VERSION 5.7 ;
  NOWIREEXTENSIONATPIN ON ;
  DIVIDERCHAR "/" ;
  BUSBITCHARS "[]" ;
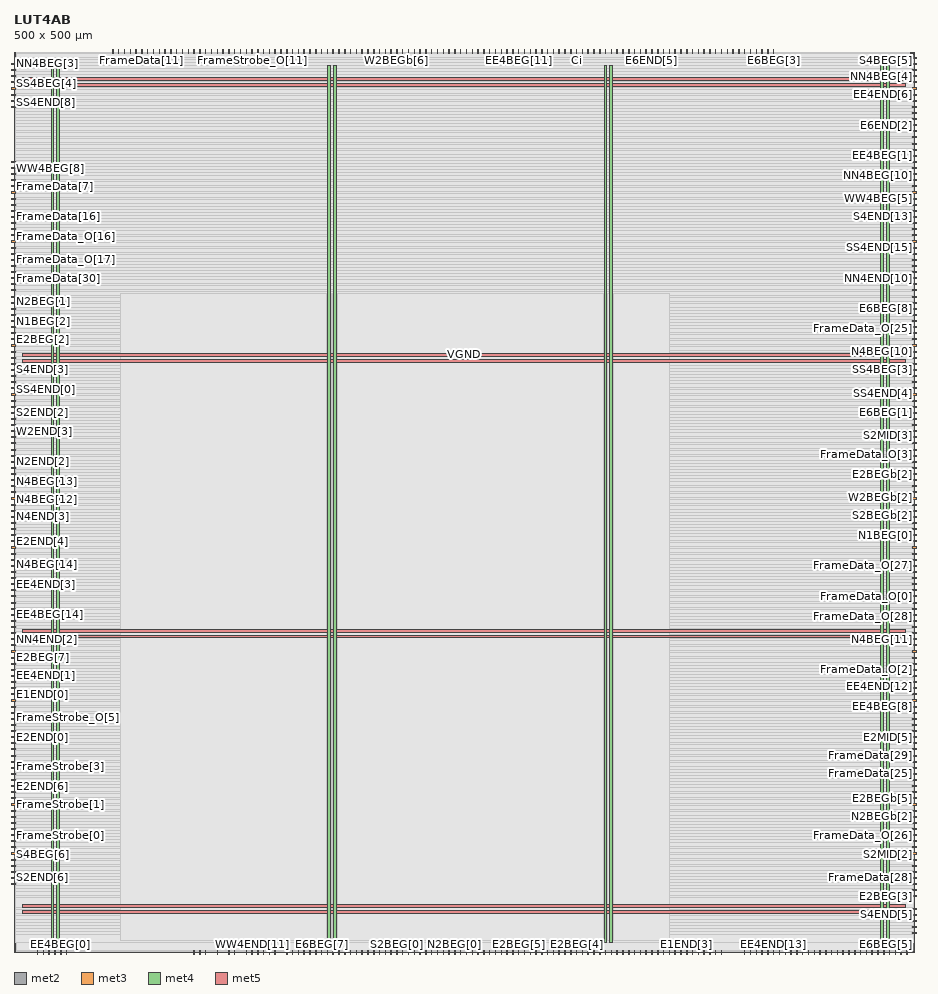
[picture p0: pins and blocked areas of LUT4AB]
MACRO LUT4AB
  CLASS BLOCK ;
  FOREIGN LUT4AB ;
  ORIGIN 0.000 0.000 ;
  SIZE 500.000 BY 500.000 ;
  PIN Ci
    DIRECTION INPUT ;
    USE SIGNAL ;
    ANTENNAGATEAREA 0.742500 ;
    PORT
      LAYER met2 ;
        RECT 312.430 499.200 312.710 501.500 ;
    END
  END Ci
  PIN Co
    DIRECTION OUTPUT ;
    USE SIGNAL ;
    ANTENNADIFFAREA 0.445500 ;
    PORT
      LAYER met2 ;
        RECT 235.150 499.200 235.430 501.500 ;
    END
  END Co
  PIN E1BEG[0]
    DIRECTION OUTPUT ;
    USE SIGNAL ;
    ANTENNADIFFAREA 1.336500 ;
    PORT
      LAYER met2 ;
        RECT 296.330 499.200 296.610 501.500 ;
    END
  END E1BEG[0]
  PIN E1BEG[1]
    DIRECTION OUTPUT ;
    USE SIGNAL ;
    ANTENNADIFFAREA 0.445500 ;
    PORT
      LAYER met2 ;
        RECT 257.690 -1.500 257.970 0.800 ;
    END
  END E1BEG[1]
  PIN E1BEG[2]
    DIRECTION OUTPUT ;
    USE SIGNAL ;
    ANTENNADIFFAREA 1.782000 ;
    PORT
      LAYER met3 ;
        RECT -1.500 438.640 0.800 439.240 ;
    END
  END E1BEG[2]
  PIN E1BEG[3]
    DIRECTION OUTPUT ;
    USE SIGNAL ;
    ANTENNADIFFAREA 1.336500 ;
    PORT
      LAYER met2 ;
        RECT 206.170 499.200 206.450 501.500 ;
    END
  END E1BEG[3]
  PIN E1END[0]
    DIRECTION INPUT ;
    USE SIGNAL ;
    ANTENNAGATEAREA 0.247500 ;
    PORT
      LAYER met3 ;
        RECT -1.500 142.840 0.800 143.440 ;
    END
  END E1END[0]
  PIN E1END[1]
    DIRECTION INPUT ;
    USE SIGNAL ;
    ANTENNAGATEAREA 0.426000 ;
    PORT
      LAYER met2 ;
        RECT 141.770 -1.500 142.050 0.800 ;
    END
  END E1END[1]
  PIN E1END[2]
    DIRECTION INPUT ;
    USE SIGNAL ;
    ANTENNAGATEAREA 0.159000 ;
    PORT
      LAYER met3 ;
        RECT -1.500 37.440 0.800 38.040 ;
    END
  END E1END[2]
  PIN E1END[3]
    DIRECTION INPUT ;
    USE SIGNAL ;
    ANTENNAGATEAREA 0.126000 ;
    PORT
      LAYER met2 ;
        RECT 373.610 -1.500 373.890 0.800 ;
    END
  END E1END[3]
  PIN E2BEG[0]
    DIRECTION OUTPUT ;
    USE SIGNAL ;
    ANTENNADIFFAREA 1.782000 ;
    PORT
      LAYER met2 ;
        RECT 151.430 -1.500 151.710 0.800 ;
    END
  END E2BEG[0]
  PIN E2BEG[1]
    DIRECTION OUTPUT ;
    USE SIGNAL ;
    ANTENNADIFFAREA 1.782000 ;
    PORT
      LAYER met3 ;
        RECT -1.500 346.840 0.800 347.440 ;
    END
  END E2BEG[1]
  PIN E2BEG[2]
    DIRECTION OUTPUT ;
    USE SIGNAL ;
    ANTENNADIFFAREA 1.782000 ;
    PORT
      LAYER met3 ;
        RECT -1.500 340.040 0.800 340.640 ;
    END
  END E2BEG[2]
  PIN E2BEG[3]
    DIRECTION OUTPUT ;
    USE SIGNAL ;
    ANTENNADIFFAREA 0.445500 ;
    PORT
      LAYER met3 ;
        RECT 499.200 30.640 501.500 31.240 ;
    END
  END E2BEG[3]
  PIN E2BEG[4]
    DIRECTION OUTPUT ;
    USE SIGNAL ;
    ANTENNADIFFAREA 1.782000 ;
    PORT
      LAYER met2 ;
        RECT 312.430 -1.500 312.710 0.800 ;
    END
  END E2BEG[4]
  PIN E2BEG[5]
    DIRECTION OUTPUT ;
    USE SIGNAL ;
    ANTENNADIFFAREA 0.445500 ;
    PORT
      LAYER met2 ;
        RECT 280.230 -1.500 280.510 0.800 ;
    END
  END E2BEG[5]
  PIN E2BEG[6]
    DIRECTION OUTPUT ;
    USE SIGNAL ;
    ANTENNADIFFAREA 1.782000 ;
    PORT
      LAYER met2 ;
        RECT 363.950 -1.500 364.230 0.800 ;
    END
  END E2BEG[6]
  PIN E2BEG[7]
    DIRECTION OUTPUT ;
    USE SIGNAL ;
    ANTENNADIFFAREA 1.336500 ;
    PORT
      LAYER met3 ;
        RECT -1.500 163.240 0.800 163.840 ;
    END
  END E2BEG[7]
  PIN E2BEGb[0]
    DIRECTION OUTPUT ;
    USE SIGNAL ;
    ANTENNADIFFAREA 0.445500 ;
    PORT
      LAYER met2 ;
        RECT 293.110 499.200 293.390 501.500 ;
    END
  END E2BEGb[0]
  PIN E2BEGb[1]
    DIRECTION OUTPUT ;
    USE SIGNAL ;
    ANTENNADIFFAREA 0.445500 ;
    PORT
      LAYER met2 ;
        RECT 254.470 499.200 254.750 501.500 ;
    END
  END E2BEGb[1]
  PIN E2BEGb[2]
    DIRECTION OUTPUT ;
    USE SIGNAL ;
    ANTENNADIFFAREA 0.445500 ;
    PORT
      LAYER met3 ;
        RECT 499.200 265.240 501.500 265.840 ;
    END
  END E2BEGb[2]
  PIN E2BEGb[3]
    DIRECTION OUTPUT ;
    USE SIGNAL ;
    ANTENNADIFFAREA 0.445500 ;
    PORT
      LAYER met3 ;
        RECT 499.200 34.040 501.500 34.640 ;
    END
  END E2BEGb[3]
  PIN E2BEGb[4]
    DIRECTION OUTPUT ;
    USE SIGNAL ;
    ANTENNADIFFAREA 0.445500 ;
    PORT
      LAYER met2 ;
        RECT 277.010 -1.500 277.290 0.800 ;
    END
  END E2BEGb[4]
  PIN E2BEGb[5]
    DIRECTION OUTPUT ;
    USE SIGNAL ;
    ANTENNADIFFAREA 0.445500 ;
    PORT
      LAYER met3 ;
        RECT 499.200 85.040 501.500 85.640 ;
    END
  END E2BEGb[5]
  PIN E2BEGb[6]
    DIRECTION OUTPUT ;
    USE SIGNAL ;
    ANTENNADIFFAREA 0.445500 ;
    PORT
      LAYER met2 ;
        RECT 228.710 499.200 228.990 501.500 ;
    END
  END E2BEGb[6]
  PIN E2BEGb[7]
    DIRECTION OUTPUT ;
    USE SIGNAL ;
    ANTENNADIFFAREA 0.445500 ;
    PORT
      LAYER met2 ;
        RECT 54.830 499.200 55.110 501.500 ;
    END
  END E2BEGb[7]
  PIN E2END[0]
    DIRECTION INPUT ;
    USE SIGNAL ;
    ANTENNAGATEAREA 0.213000 ;
    PORT
      LAYER met3 ;
        RECT -1.500 119.040 0.800 119.640 ;
    END
  END E2END[0]
  PIN E2END[1]
    DIRECTION INPUT ;
    USE SIGNAL ;
    ANTENNAGATEAREA 0.213000 ;
    PORT
      LAYER met2 ;
        RECT 209.390 -1.500 209.670 0.800 ;
    END
  END E2END[1]
  PIN E2END[2]
    DIRECTION INPUT ;
    USE SIGNAL ;
    ANTENNAGATEAREA 0.159000 ;
    PORT
      LAYER met3 ;
        RECT -1.500 251.640 0.800 252.240 ;
    END
  END E2END[2]
  PIN E2END[3]
    DIRECTION INPUT ;
    USE SIGNAL ;
    ANTENNAGATEAREA 0.159000 ;
    PORT
      LAYER met3 ;
        RECT -1.500 309.440 0.800 310.040 ;
    END
  END E2END[3]
  PIN E2END[4]
    DIRECTION INPUT ;
    USE SIGNAL ;
    ANTENNAGATEAREA 0.213000 ;
    PORT
      LAYER met3 ;
        RECT -1.500 227.840 0.800 228.440 ;
    END
  END E2END[4]
  PIN E2END[5]
    DIRECTION INPUT ;
    USE SIGNAL ;
    ANTENNAGATEAREA 0.159000 ;
    PORT
      LAYER met2 ;
        RECT 315.650 -1.500 315.930 0.800 ;
    END
  END E2END[5]
  PIN E2END[6]
    DIRECTION INPUT ;
    USE SIGNAL ;
    ANTENNAGATEAREA 0.159000 ;
    PORT
      LAYER met3 ;
        RECT -1.500 91.840 0.800 92.440 ;
    END
  END E2END[6]
  PIN E2END[7]
    DIRECTION INPUT ;
    USE SIGNAL ;
    ANTENNAGATEAREA 0.159000 ;
    PORT
      LAYER met2 ;
        RECT 328.530 -1.500 328.810 0.800 ;
    END
  END E2END[7]
  PIN E2MID[0]
    DIRECTION INPUT ;
    USE SIGNAL ;
    ANTENNAGATEAREA 0.213000 ;
    PORT
      LAYER met2 ;
        RECT 264.130 499.200 264.410 501.500 ;
    END
  END E2MID[0]
  PIN E2MID[1]
    DIRECTION INPUT ;
    USE SIGNAL ;
    ANTENNAGATEAREA 0.196500 ;
    PORT
      LAYER met2 ;
        RECT 299.550 499.200 299.830 501.500 ;
    END
  END E2MID[1]
  PIN E2MID[2]
    DIRECTION INPUT ;
    USE SIGNAL ;
    ANTENNAGATEAREA 0.213000 ;
    PORT
      LAYER met3 ;
        RECT 499.200 37.440 501.500 38.040 ;
    END
  END E2MID[2]
  PIN E2MID[3]
    DIRECTION INPUT ;
    USE SIGNAL ;
    ANTENNAGATEAREA 0.213000 ;
    PORT
      LAYER met3 ;
        RECT 499.200 268.640 501.500 269.240 ;
    END
  END E2MID[3]
  PIN E2MID[4]
    DIRECTION INPUT ;
    USE SIGNAL ;
    ANTENNAGATEAREA 0.213000 ;
    PORT
      LAYER met2 ;
        RECT 302.770 -1.500 303.050 0.800 ;
    END
  END E2MID[4]
  PIN E2MID[5]
    DIRECTION INPUT ;
    USE SIGNAL ;
    ANTENNAGATEAREA 0.159000 ;
    PORT
      LAYER met3 ;
        RECT 499.200 119.040 501.500 119.640 ;
    END
  END E2MID[5]
  PIN E2MID[6]
    DIRECTION INPUT ;
    USE SIGNAL ;
    ANTENNAGATEAREA 0.213000 ;
    PORT
      LAYER met2 ;
        RECT 225.490 499.200 225.770 501.500 ;
    END
  END E2MID[6]
  PIN E2MID[7]
    DIRECTION INPUT ;
    USE SIGNAL ;
    ANTENNAGATEAREA 0.213000 ;
    PORT
      LAYER met2 ;
        RECT 151.430 499.200 151.710 501.500 ;
    END
  END E2MID[7]
  PIN E6BEG[0]
    DIRECTION OUTPUT ;
    USE SIGNAL ;
    ANTENNADIFFAREA 0.445500 ;
    PORT
      LAYER met3 ;
        RECT 499.200 312.840 501.500 313.440 ;
    END
  END E6BEG[0]
  PIN E6BEG[10]
    DIRECTION OUTPUT ;
    USE SIGNAL ;
    ANTENNADIFFAREA 0.891000 ;
    PORT
      LAYER met3 ;
        RECT 499.200 122.440 501.500 123.040 ;
    END
  END E6BEG[10]
  PIN E6BEG[11]
    DIRECTION OUTPUT ;
    USE SIGNAL ;
    ANTENNADIFFAREA 1.782000 ;
    PORT
      LAYER met3 ;
        RECT 499.200 200.640 501.500 201.240 ;
    END
  END E6BEG[11]
  PIN E6BEG[1]
    DIRECTION OUTPUT ;
    USE SIGNAL ;
    ANTENNADIFFAREA 0.445500 ;
    PORT
      LAYER met3 ;
        RECT 499.200 299.240 501.500 299.840 ;
    END
  END E6BEG[1]
  PIN E6BEG[2]
    DIRECTION OUTPUT ;
    USE SIGNAL ;
    ANTENNADIFFAREA 0.445500 ;
    PORT
      LAYER met2 ;
        RECT 170.750 499.200 171.030 501.500 ;
    END
  END E6BEG[2]
  PIN E6BEG[3]
    DIRECTION OUTPUT ;
    USE SIGNAL ;
    ANTENNADIFFAREA 0.445500 ;
    PORT
      LAYER met2 ;
        RECT 421.910 499.200 422.190 501.500 ;
    END
  END E6BEG[3]
  PIN E6BEG[4]
    DIRECTION OUTPUT ;
    USE SIGNAL ;
    ANTENNADIFFAREA 0.445500 ;
    PORT
      LAYER met3 ;
        RECT 499.200 78.240 501.500 78.840 ;
    END
  END E6BEG[4]
  PIN E6BEG[5]
    DIRECTION OUTPUT ;
    USE SIGNAL ;
    ANTENNADIFFAREA 0.445500 ;
    PORT
      LAYER met2 ;
        RECT 495.970 -1.500 496.250 0.800 ;
    END
  END E6BEG[5]
  PIN E6BEG[6]
    DIRECTION OUTPUT ;
    USE SIGNAL ;
    ANTENNADIFFAREA 0.445500 ;
    PORT
      LAYER met2 ;
        RECT 202.950 499.200 203.230 501.500 ;
    END
  END E6BEG[6]
  PIN E6BEG[7]
    DIRECTION OUTPUT ;
    USE SIGNAL ;
    ANTENNADIFFAREA 0.445500 ;
    PORT
      LAYER met2 ;
        RECT 170.750 -1.500 171.030 0.800 ;
    END
  END E6BEG[7]
  PIN E6BEG[8]
    DIRECTION OUTPUT ;
    USE SIGNAL ;
    ANTENNADIFFAREA 0.445500 ;
    PORT
      LAYER met3 ;
        RECT 499.200 357.040 501.500 357.640 ;
    END
  END E6BEG[8]
  PIN E6BEG[9]
    DIRECTION OUTPUT ;
    USE SIGNAL ;
    ANTENNADIFFAREA 0.445500 ;
    PORT
      LAYER met2 ;
        RECT 67.710 499.200 67.990 501.500 ;
    END
  END E6BEG[9]
  PIN E6END[0]
    DIRECTION INPUT ;
    USE SIGNAL ;
    ANTENNAGATEAREA 0.159000 ;
    PORT
      LAYER met3 ;
        RECT -1.500 329.840 0.800 330.440 ;
    END
  END E6END[0]
  PIN E6END[10]
    DIRECTION INPUT ;
    USE SIGNAL ;
    ANTENNAGATEAREA 0.631200 ;
    ANTENNADIFFAREA 0.434700 ;
    PORT
      LAYER met3 ;
        RECT 499.200 472.640 501.500 473.240 ;
    END
  END E6END[10]
  PIN E6END[11]
    DIRECTION INPUT ;
    USE SIGNAL ;
    ANTENNAGATEAREA 0.196500 ;
    PORT
      LAYER met2 ;
        RECT 74.150 499.200 74.430 501.500 ;
    END
  END E6END[11]
  PIN E6END[1]
    DIRECTION INPUT ;
    USE SIGNAL ;
    ANTENNAGATEAREA 0.159000 ;
    PORT
      LAYER met3 ;
        RECT -1.500 115.640 0.800 116.240 ;
    END
  END E6END[1]
  PIN E6END[2]
    DIRECTION INPUT ;
    USE SIGNAL ;
    ANTENNAGATEAREA 0.213000 ;
    PORT
      LAYER met3 ;
        RECT 499.200 459.040 501.500 459.640 ;
    END
  END E6END[2]
  PIN E6END[3]
    DIRECTION INPUT ;
    USE SIGNAL ;
    ANTENNAGATEAREA 0.196500 ;
    PORT
      LAYER met3 ;
        RECT 499.200 302.640 501.500 303.240 ;
    END
  END E6END[3]
  PIN E6END[4]
    DIRECTION INPUT ;
    USE SIGNAL ;
    ANTENNAGATEAREA 0.196500 ;
    PORT
      LAYER met2 ;
        RECT 183.630 499.200 183.910 501.500 ;
    END
  END E6END[4]
  PIN E6END[5]
    DIRECTION INPUT ;
    USE SIGNAL ;
    ANTENNAGATEAREA 0.196500 ;
    PORT
      LAYER met2 ;
        RECT 354.290 499.200 354.570 501.500 ;
    END
  END E6END[5]
  PIN E6END[6]
    DIRECTION INPUT ;
    USE SIGNAL ;
    ANTENNAGATEAREA 0.213000 ;
    PORT
      LAYER met3 ;
        RECT 499.200 234.640 501.500 235.240 ;
    END
  END E6END[6]
  PIN E6END[7]
    DIRECTION INPUT ;
    USE SIGNAL ;
    ANTENNAGATEAREA 0.196500 ;
    PORT
      LAYER met2 ;
        RECT 476.650 -1.500 476.930 0.800 ;
    END
  END E6END[7]
  PIN E6END[8]
    DIRECTION INPUT ;
    USE SIGNAL ;
    ANTENNAGATEAREA 0.196500 ;
    PORT
      LAYER met2 ;
        RECT 173.970 499.200 174.250 501.500 ;
    END
  END E6END[8]
  PIN E6END[9]
    DIRECTION INPUT ;
    USE SIGNAL ;
    ANTENNAGATEAREA 0.196500 ;
    PORT
      LAYER met2 ;
        RECT 215.830 -1.500 216.110 0.800 ;
    END
  END E6END[9]
  PIN EE4BEG[0]
    DIRECTION OUTPUT ;
    USE SIGNAL ;
    ANTENNADIFFAREA 0.445500 ;
    PORT
      LAYER met2 ;
        RECT 25.850 -1.500 26.130 0.800 ;
    END
  END EE4BEG[0]
  PIN EE4BEG[10]
    DIRECTION OUTPUT ;
    USE SIGNAL ;
    ANTENNADIFFAREA 0.445500 ;
    PORT
      LAYER met2 ;
        RECT 164.310 -1.500 164.590 0.800 ;
    END
  END EE4BEG[10]
  PIN EE4BEG[11]
    DIRECTION OUTPUT ;
    USE SIGNAL ;
    ANTENNADIFFAREA 0.445500 ;
    PORT
      LAYER met2 ;
        RECT 280.230 499.200 280.510 501.500 ;
    END
  END EE4BEG[11]
  PIN EE4BEG[12]
    DIRECTION OUTPUT ;
    USE SIGNAL ;
    ANTENNADIFFAREA 1.782000 ;
    PORT
      LAYER met2 ;
        RECT 235.150 -1.500 235.430 0.800 ;
    END
  END EE4BEG[12]
  PIN EE4BEG[13]
    DIRECTION OUTPUT ;
    USE SIGNAL ;
    ANTENNADIFFAREA 1.782000 ;
    PORT
      LAYER met2 ;
        RECT 322.090 -1.500 322.370 0.800 ;
    END
  END EE4BEG[13]
  PIN EE4BEG[14]
    DIRECTION OUTPUT ;
    USE SIGNAL ;
    ANTENNADIFFAREA 1.782000 ;
    PORT
      LAYER met3 ;
        RECT -1.500 187.040 0.800 187.640 ;
    END
  END EE4BEG[14]
  PIN EE4BEG[15]
    DIRECTION OUTPUT ;
    USE SIGNAL ;
    ANTENNADIFFAREA 1.782000 ;
    PORT
      LAYER met2 ;
        RECT 309.210 -1.500 309.490 0.800 ;
    END
  END EE4BEG[15]
  PIN EE4BEG[1]
    DIRECTION OUTPUT ;
    USE SIGNAL ;
    ANTENNADIFFAREA 0.445500 ;
    PORT
      LAYER met3 ;
        RECT 499.200 442.040 501.500 442.640 ;
    END
  END EE4BEG[1]
  PIN EE4BEG[2]
    DIRECTION OUTPUT ;
    USE SIGNAL ;
    ANTENNADIFFAREA 0.445500 ;
    PORT
      LAYER met3 ;
        RECT 499.200 479.440 501.500 480.040 ;
    END
  END EE4BEG[2]
  PIN EE4BEG[3]
    DIRECTION OUTPUT ;
    USE SIGNAL ;
    ANTENNADIFFAREA 0.445500 ;
    PORT
      LAYER met3 ;
        RECT -1.500 261.840 0.800 262.440 ;
    END
  END EE4BEG[3]
  PIN EE4BEG[4]
    DIRECTION OUTPUT ;
    USE SIGNAL ;
    ANTENNADIFFAREA 0.445500 ;
    PORT
      LAYER met3 ;
        RECT 499.200 482.840 501.500 483.440 ;
    END
  END EE4BEG[4]
  PIN EE4BEG[5]
    DIRECTION OUTPUT ;
    USE SIGNAL ;
    ANTENNADIFFAREA 0.445500 ;
    PORT
      LAYER met3 ;
        RECT 499.200 10.240 501.500 10.840 ;
    END
  END EE4BEG[5]
  PIN EE4BEG[6]
    DIRECTION OUTPUT ;
    USE SIGNAL ;
    ANTENNADIFFAREA 0.445500 ;
    PORT
      LAYER met2 ;
        RECT 463.770 -1.500 464.050 0.800 ;
    END
  END EE4BEG[6]
  PIN EE4BEG[7]
    DIRECTION OUTPUT ;
    USE SIGNAL ;
    ANTENNADIFFAREA 0.445500 ;
    PORT
      LAYER met3 ;
        RECT 499.200 278.840 501.500 279.440 ;
    END
  END EE4BEG[7]
  PIN EE4BEG[8]
    DIRECTION OUTPUT ;
    USE SIGNAL ;
    ANTENNADIFFAREA 0.445500 ;
    PORT
      LAYER met3 ;
        RECT 499.200 136.040 501.500 136.640 ;
    END
  END EE4BEG[8]
  PIN EE4BEG[9]
    DIRECTION OUTPUT ;
    USE SIGNAL ;
    ANTENNADIFFAREA 0.445500 ;
    PORT
      LAYER met2 ;
        RECT 405.810 -1.500 406.090 0.800 ;
    END
  END EE4BEG[9]
  PIN EE4END[0]
    DIRECTION INPUT ;
    USE SIGNAL ;
    ANTENNAGATEAREA 0.159000 ;
    PORT
      LAYER met3 ;
        RECT -1.500 159.840 0.800 160.440 ;
    END
  END EE4END[0]
  PIN EE4END[10]
    DIRECTION INPUT ;
    USE SIGNAL ;
    ANTENNAGATEAREA 0.196500 ;
    PORT
      LAYER met2 ;
        RECT 450.890 -1.500 451.170 0.800 ;
    END
  END EE4END[10]
  PIN EE4END[11]
    DIRECTION INPUT ;
    USE SIGNAL ;
    ANTENNAGATEAREA 0.196500 ;
    PORT
      LAYER met3 ;
        RECT 499.200 292.440 501.500 293.040 ;
    END
  END EE4END[11]
  PIN EE4END[12]
    DIRECTION INPUT ;
    USE SIGNAL ;
    ANTENNAGATEAREA 0.196500 ;
    PORT
      LAYER met3 ;
        RECT 499.200 142.840 501.500 143.440 ;
    END
  END EE4END[12]
  PIN EE4END[13]
    DIRECTION INPUT ;
    USE SIGNAL ;
    ANTENNAGATEAREA 0.196500 ;
    PORT
      LAYER met2 ;
        RECT 421.910 -1.500 422.190 0.800 ;
    END
  END EE4END[13]
  PIN EE4END[14]
    DIRECTION INPUT ;
    USE SIGNAL ;
    ANTENNAGATEAREA 0.196500 ;
    PORT
      LAYER met2 ;
        RECT 167.530 -1.500 167.810 0.800 ;
    END
  END EE4END[14]
  PIN EE4END[15]
    DIRECTION INPUT ;
    USE SIGNAL ;
    ANTENNAGATEAREA 0.196500 ;
    PORT
      LAYER met2 ;
        RECT 286.670 499.200 286.950 501.500 ;
    END
  END EE4END[15]
  PIN EE4END[1]
    DIRECTION INPUT ;
    USE SIGNAL ;
    ANTENNAGATEAREA 0.159000 ;
    PORT
      LAYER met3 ;
        RECT -1.500 153.040 0.800 153.640 ;
    END
  END EE4END[1]
  PIN EE4END[2]
    DIRECTION INPUT ;
    USE SIGNAL ;
    ANTENNAGATEAREA 0.159000 ;
    PORT
      LAYER met3 ;
        RECT -1.500 190.440 0.800 191.040 ;
    END
  END EE4END[2]
  PIN EE4END[3]
    DIRECTION INPUT ;
    USE SIGNAL ;
    ANTENNAGATEAREA 0.159000 ;
    PORT
      LAYER met3 ;
        RECT -1.500 204.040 0.800 204.640 ;
    END
  END EE4END[3]
  PIN EE4END[4]
    DIRECTION INPUT ;
    USE SIGNAL ;
    ANTENNAGATEAREA 0.196500 ;
    PORT
      LAYER met2 ;
        RECT 19.410 -1.500 19.690 0.800 ;
    END
  END EE4END[4]
  PIN EE4END[5]
    DIRECTION INPUT ;
    USE SIGNAL ;
    ANTENNAGATEAREA 0.196500 ;
    PORT
      LAYER met3 ;
        RECT 499.200 445.440 501.500 446.040 ;
    END
  END EE4END[5]
  PIN EE4END[6]
    DIRECTION INPUT ;
    USE SIGNAL ;
    ANTENNAGATEAREA 0.196500 ;
    PORT
      LAYER met3 ;
        RECT 499.200 476.040 501.500 476.640 ;
    END
  END EE4END[6]
  PIN EE4END[7]
    DIRECTION INPUT ;
    USE SIGNAL ;
    ANTENNAGATEAREA 0.196500 ;
    PORT
      LAYER met3 ;
        RECT -1.500 258.440 0.800 259.040 ;
    END
  END EE4END[7]
  PIN EE4END[8]
    DIRECTION INPUT ;
    USE SIGNAL ;
    ANTENNAGATEAREA 0.196500 ;
    PORT
      LAYER met3 ;
        RECT 499.200 469.240 501.500 469.840 ;
    END
  END EE4END[8]
  PIN EE4END[9]
    DIRECTION INPUT ;
    USE SIGNAL ;
    ANTENNAGATEAREA 0.196500 ;
    PORT
      LAYER met2 ;
        RECT 489.530 -1.500 489.810 0.800 ;
    END
  END EE4END[9]
  PIN FrameData[0]
    DIRECTION INPUT ;
    USE SIGNAL ;
    ANTENNAGATEAREA 0.126000 ;
    PORT
      LAYER met3 ;
        RECT 499.200 47.640 501.500 48.240 ;
    END
  END FrameData[0]
  PIN FrameData[10]
    DIRECTION INPUT ;
    USE SIGNAL ;
    ANTENNAGATEAREA 0.213000 ;
    PORT
      LAYER met3 ;
        RECT -1.500 431.840 0.800 432.440 ;
    END
  END FrameData[10]
  PIN FrameData[11]
    DIRECTION INPUT ;
    USE SIGNAL ;
    ANTENNAGATEAREA 0.213000 ;
    PORT
      LAYER met2 ;
        RECT 70.930 499.200 71.210 501.500 ;
    END
  END FrameData[11]
  PIN FrameData[12]
    DIRECTION INPUT ;
    USE SIGNAL ;
    ANTENNAGATEAREA 0.159000 ;
    PORT
      LAYER met2 ;
        RECT 80.590 499.200 80.870 501.500 ;
    END
  END FrameData[12]
  PIN FrameData[13]
    DIRECTION INPUT ;
    USE SIGNAL ;
    ANTENNAGATEAREA 0.213000 ;
    PORT
      LAYER met2 ;
        RECT 99.910 -1.500 100.190 0.800 ;
    END
  END FrameData[13]
  PIN FrameData[14]
    DIRECTION INPUT ;
    USE SIGNAL ;
    ANTENNAGATEAREA 0.196500 ;
    PORT
      LAYER met2 ;
        RECT 119.230 -1.500 119.510 0.800 ;
    END
  END FrameData[14]
  PIN FrameData[15]
    DIRECTION INPUT ;
    USE SIGNAL ;
    ANTENNAGATEAREA 0.213000 ;
    PORT
      LAYER met2 ;
        RECT 122.450 -1.500 122.730 0.800 ;
    END
  END FrameData[15]
  PIN FrameData[16]
    DIRECTION INPUT ;
    USE SIGNAL ;
    ANTENNAGATEAREA 0.213000 ;
    PORT
      LAYER met3 ;
        RECT -1.500 408.040 0.800 408.640 ;
    END
  END FrameData[16]
  PIN FrameData[17]
    DIRECTION INPUT ;
    USE SIGNAL ;
    ANTENNAGATEAREA 0.196500 ;
    PORT
      LAYER met3 ;
        RECT -1.500 394.440 0.800 395.040 ;
    END
  END FrameData[17]
  PIN FrameData[18]
    DIRECTION INPUT ;
    USE SIGNAL ;
    ANTENNAGATEAREA 0.126000 ;
    PORT
      LAYER met3 ;
        RECT -1.500 387.640 0.800 388.240 ;
    END
  END FrameData[18]
  PIN FrameData[19]
    DIRECTION INPUT ;
    USE SIGNAL ;
    ANTENNAGATEAREA 0.213000 ;
    PORT
      LAYER met3 ;
        RECT -1.500 397.840 0.800 398.440 ;
    END
  END FrameData[19]
  PIN FrameData[1]
    DIRECTION INPUT ;
    USE SIGNAL ;
    ANTENNAGATEAREA 0.196500 ;
    PORT
      LAYER met2 ;
        RECT 415.470 499.200 415.750 501.500 ;
    END
  END FrameData[1]
  PIN FrameData[20]
    DIRECTION INPUT ;
    USE SIGNAL ;
    ANTENNAGATEAREA 0.213000 ;
    PORT
      LAYER met2 ;
        RECT 112.790 -1.500 113.070 0.800 ;
    END
  END FrameData[20]
  PIN FrameData[21]
    DIRECTION INPUT ;
    USE SIGNAL ;
    ANTENNAGATEAREA 0.196500 ;
    PORT
      LAYER met2 ;
        RECT 392.930 -1.500 393.210 0.800 ;
    END
  END FrameData[21]
  PIN FrameData[22]
    DIRECTION INPUT ;
    USE SIGNAL ;
    ANTENNAGATEAREA 0.159000 ;
    PORT
      LAYER met2 ;
        RECT 380.050 -1.500 380.330 0.800 ;
    END
  END FrameData[22]
  PIN FrameData[23]
    DIRECTION INPUT ;
    USE SIGNAL ;
    ANTENNAGATEAREA 0.213000 ;
    PORT
      LAYER met3 ;
        RECT -1.500 95.240 0.800 95.840 ;
    END
  END FrameData[23]
  PIN FrameData[24]
    DIRECTION INPUT ;
    USE SIGNAL ;
    ANTENNAGATEAREA 0.213000 ;
    PORT
      LAYER met2 ;
        RECT 138.550 -1.500 138.830 0.800 ;
    END
  END FrameData[24]
  PIN FrameData[25]
    DIRECTION INPUT ;
    USE SIGNAL ;
    ANTENNAGATEAREA 0.213000 ;
    PORT
      LAYER met3 ;
        RECT 499.200 98.640 501.500 99.240 ;
    END
  END FrameData[25]
  PIN FrameData[26]
    DIRECTION INPUT ;
    USE SIGNAL ;
    ANTENNAGATEAREA 0.196500 ;
    PORT
      LAYER met3 ;
        RECT 499.200 54.440 501.500 55.040 ;
    END
  END FrameData[26]
  PIN FrameData[27]
    DIRECTION INPUT ;
    USE SIGNAL ;
    ANTENNAGATEAREA 0.126000 ;
    PORT
      LAYER met3 ;
        RECT 499.200 102.040 501.500 102.640 ;
    END
  END FrameData[27]
  PIN FrameData[28]
    DIRECTION INPUT ;
    USE SIGNAL ;
    ANTENNAGATEAREA 0.126000 ;
    PORT
      LAYER met3 ;
        RECT 499.200 40.840 501.500 41.440 ;
    END
  END FrameData[28]
  PIN FrameData[29]
    DIRECTION INPUT ;
    USE SIGNAL ;
    ANTENNAGATEAREA 0.196500 ;
    PORT
      LAYER met3 ;
        RECT 499.200 108.840 501.500 109.440 ;
    END
  END FrameData[29]
  PIN FrameData[2]
    DIRECTION INPUT ;
    USE SIGNAL ;
    ANTENNAGATEAREA 0.213000 ;
    PORT
      LAYER met3 ;
        RECT -1.500 404.640 0.800 405.240 ;
    END
  END FrameData[2]
  PIN FrameData[30]
    DIRECTION INPUT ;
    USE SIGNAL ;
    ANTENNAGATEAREA 0.196500 ;
    PORT
      LAYER met3 ;
        RECT -1.500 374.040 0.800 374.640 ;
    END
  END FrameData[30]
  PIN FrameData[31]
    DIRECTION INPUT ;
    USE SIGNAL ;
    ANTENNAGATEAREA 0.196500 ;
    PORT
      LAYER met2 ;
        RECT 344.630 499.200 344.910 501.500 ;
    END
  END FrameData[31]
  PIN FrameData[3]
    DIRECTION INPUT ;
    USE SIGNAL ;
    ANTENNAGATEAREA 0.159000 ;
    PORT
      LAYER met2 ;
        RECT 360.730 499.200 361.010 501.500 ;
    END
  END FrameData[3]
  PIN FrameData[4]
    DIRECTION INPUT ;
    USE SIGNAL ;
    ANTENNAGATEAREA 0.213000 ;
    PORT
      LAYER met2 ;
        RECT 90.250 499.200 90.530 501.500 ;
    END
  END FrameData[4]
  PIN FrameData[5]
    DIRECTION INPUT ;
    USE SIGNAL ;
    ANTENNAGATEAREA 0.213000 ;
    PORT
      LAYER met2 ;
        RECT 109.570 499.200 109.850 501.500 ;
    END
  END FrameData[5]
  PIN FrameData[6]
    DIRECTION INPUT ;
    USE SIGNAL ;
    ANTENNAGATEAREA 0.196500 ;
    PORT
      LAYER met2 ;
        RECT 418.690 499.200 418.970 501.500 ;
    END
  END FrameData[6]
  PIN FrameData[7]
    DIRECTION INPUT ;
    USE SIGNAL ;
    ANTENNAGATEAREA 0.213000 ;
    PORT
      LAYER met3 ;
        RECT -1.500 425.040 0.800 425.640 ;
    END
  END FrameData[7]
  PIN FrameData[8]
    DIRECTION INPUT ;
    USE SIGNAL ;
    ANTENNAGATEAREA 0.213000 ;
    PORT
      LAYER met2 ;
        RECT 77.370 499.200 77.650 501.500 ;
    END
  END FrameData[8]
  PIN FrameData[9]
    DIRECTION INPUT ;
    USE SIGNAL ;
    ANTENNAGATEAREA 0.213000 ;
    PORT
      LAYER met3 ;
        RECT -1.500 421.640 0.800 422.240 ;
    END
  END FrameData[9]
  PIN FrameData_O[0]
    DIRECTION OUTPUT ;
    USE SIGNAL ;
    ANTENNADIFFAREA 0.445500 ;
    PORT
      LAYER met3 ;
        RECT 499.200 197.240 501.500 197.840 ;
    END
  END FrameData_O[0]
  PIN FrameData_O[10]
    DIRECTION OUTPUT ;
    USE SIGNAL ;
    ANTENNADIFFAREA 0.445500 ;
    PORT
      LAYER met2 ;
        RECT 83.810 499.200 84.090 501.500 ;
    END
  END FrameData_O[10]
  PIN FrameData_O[11]
    DIRECTION OUTPUT ;
    USE SIGNAL ;
    ANTENNADIFFAREA 0.445500 ;
    PORT
      LAYER met2 ;
        RECT 87.030 499.200 87.310 501.500 ;
    END
  END FrameData_O[11]
  PIN FrameData_O[12]
    DIRECTION OUTPUT ;
    USE SIGNAL ;
    ANTENNADIFFAREA 0.445500 ;
    PORT
      LAYER met2 ;
        RECT 64.490 499.200 64.770 501.500 ;
    END
  END FrameData_O[12]
  PIN FrameData_O[13]
    DIRECTION OUTPUT ;
    USE SIGNAL ;
    ANTENNADIFFAREA 0.445500 ;
    PORT
      LAYER met3 ;
        RECT -1.500 380.840 0.800 381.440 ;
    END
  END FrameData_O[13]
  PIN FrameData_O[14]
    DIRECTION OUTPUT ;
    USE SIGNAL ;
    ANTENNADIFFAREA 0.445500 ;
    PORT
      LAYER met2 ;
        RECT 125.670 499.200 125.950 501.500 ;
    END
  END FrameData_O[14]
  PIN FrameData_O[15]
    DIRECTION OUTPUT ;
    USE SIGNAL ;
    ANTENNADIFFAREA 0.445500 ;
    PORT
      LAYER met2 ;
        RECT 341.410 499.200 341.690 501.500 ;
    END
  END FrameData_O[15]
  PIN FrameData_O[16]
    DIRECTION OUTPUT ;
    USE SIGNAL ;
    ANTENNADIFFAREA 0.445500 ;
    PORT
      LAYER met3 ;
        RECT -1.500 401.240 0.800 401.840 ;
    END
  END FrameData_O[16]
  PIN FrameData_O[17]
    DIRECTION OUTPUT ;
    USE SIGNAL ;
    ANTENNADIFFAREA 0.445500 ;
    PORT
      LAYER met3 ;
        RECT -1.500 384.240 0.800 384.840 ;
    END
  END FrameData_O[17]
  PIN FrameData_O[18]
    DIRECTION OUTPUT ;
    USE SIGNAL ;
    ANTENNADIFFAREA 0.445500 ;
    PORT
      LAYER met2 ;
        RECT 373.610 499.200 373.890 501.500 ;
    END
  END FrameData_O[18]
  PIN FrameData_O[19]
    DIRECTION OUTPUT ;
    USE SIGNAL ;
    ANTENNADIFFAREA 0.445500 ;
    PORT
      LAYER met2 ;
        RECT 376.830 499.200 377.110 501.500 ;
    END
  END FrameData_O[19]
  PIN FrameData_O[1]
    DIRECTION OUTPUT ;
    USE SIGNAL ;
    ANTENNADIFFAREA 0.445500 ;
    PORT
      LAYER met2 ;
        RECT 363.950 499.200 364.230 501.500 ;
    END
  END FrameData_O[1]
  PIN FrameData_O[20]
    DIRECTION OUTPUT ;
    USE SIGNAL ;
    ANTENNADIFFAREA 0.445500 ;
    PORT
      LAYER met2 ;
        RECT 389.710 -1.500 389.990 0.800 ;
    END
  END FrameData_O[20]
  PIN FrameData_O[21]
    DIRECTION OUTPUT ;
    USE SIGNAL ;
    ANTENNADIFFAREA 0.445500 ;
    PORT
      LAYER met3 ;
        RECT 499.200 183.640 501.500 184.240 ;
    END
  END FrameData_O[21]
  PIN FrameData_O[22]
    DIRECTION OUTPUT ;
    USE SIGNAL ;
    ANTENNADIFFAREA 0.445500 ;
    PORT
      LAYER met2 ;
        RECT 386.490 -1.500 386.770 0.800 ;
    END
  END FrameData_O[22]
  PIN FrameData_O[23]
    DIRECTION OUTPUT ;
    USE SIGNAL ;
    ANTENNADIFFAREA 0.445500 ;
    PORT
      LAYER met3 ;
        RECT 499.200 105.440 501.500 106.040 ;
    END
  END FrameData_O[23]
  PIN FrameData_O[24]
    DIRECTION OUTPUT ;
    USE SIGNAL ;
    ANTENNADIFFAREA 0.445500 ;
    PORT
      LAYER met2 ;
        RECT 383.270 -1.500 383.550 0.800 ;
    END
  END FrameData_O[24]
  PIN FrameData_O[25]
    DIRECTION OUTPUT ;
    USE SIGNAL ;
    ANTENNADIFFAREA 0.445500 ;
    PORT
      LAYER met3 ;
        RECT 499.200 350.240 501.500 350.840 ;
    END
  END FrameData_O[25]
  PIN FrameData_O[26]
    DIRECTION OUTPUT ;
    USE SIGNAL ;
    ANTENNADIFFAREA 0.445500 ;
    PORT
      LAYER met3 ;
        RECT 499.200 64.640 501.500 65.240 ;
    END
  END FrameData_O[26]
  PIN FrameData_O[27]
    DIRECTION OUTPUT ;
    USE SIGNAL ;
    ANTENNADIFFAREA 0.445500 ;
    PORT
      LAYER met3 ;
        RECT 499.200 214.240 501.500 214.840 ;
    END
  END FrameData_O[27]
  PIN FrameData_O[28]
    DIRECTION OUTPUT ;
    USE SIGNAL ;
    ANTENNADIFFAREA 0.445500 ;
    PORT
      LAYER met3 ;
        RECT 499.200 190.440 501.500 191.040 ;
    END
  END FrameData_O[28]
  PIN FrameData_O[29]
    DIRECTION OUTPUT ;
    USE SIGNAL ;
    ANTENNADIFFAREA 0.445500 ;
    PORT
      LAYER met3 ;
        RECT 499.200 187.040 501.500 187.640 ;
    END
  END FrameData_O[29]
  PIN FrameData_O[2]
    DIRECTION OUTPUT ;
    USE SIGNAL ;
    ANTENNADIFFAREA 0.445500 ;
    PORT
      LAYER met3 ;
        RECT 499.200 156.440 501.500 157.040 ;
    END
  END FrameData_O[2]
  PIN FrameData_O[30]
    DIRECTION OUTPUT ;
    USE SIGNAL ;
    ANTENNADIFFAREA 0.445500 ;
    PORT
      LAYER met3 ;
        RECT -1.500 363.840 0.800 364.440 ;
    END
  END FrameData_O[30]
  PIN FrameData_O[31]
    DIRECTION OUTPUT ;
    USE SIGNAL ;
    ANTENNADIFFAREA 0.445500 ;
    PORT
      LAYER met2 ;
        RECT 190.070 499.200 190.350 501.500 ;
    END
  END FrameData_O[31]
  PIN FrameData_O[3]
    DIRECTION OUTPUT ;
    USE SIGNAL ;
    ANTENNADIFFAREA 0.445500 ;
    PORT
      LAYER met3 ;
        RECT 499.200 272.040 501.500 272.640 ;
    END
  END FrameData_O[3]
  PIN FrameData_O[4]
    DIRECTION OUTPUT ;
    USE SIGNAL ;
    ANTENNADIFFAREA 0.445500 ;
    PORT
      LAYER met2 ;
        RECT 357.510 499.200 357.790 501.500 ;
    END
  END FrameData_O[4]
  PIN FrameData_O[5]
    DIRECTION OUTPUT ;
    USE SIGNAL ;
    ANTENNADIFFAREA 0.445500 ;
    PORT
      LAYER met2 ;
        RECT 347.850 499.200 348.130 501.500 ;
    END
  END FrameData_O[5]
  PIN FrameData_O[6]
    DIRECTION OUTPUT ;
    USE SIGNAL ;
    ANTENNADIFFAREA 0.445500 ;
    PORT
      LAYER met2 ;
        RECT 351.070 499.200 351.350 501.500 ;
    END
  END FrameData_O[6]
  PIN FrameData_O[7]
    DIRECTION OUTPUT ;
    USE SIGNAL ;
    ANTENNADIFFAREA 0.445500 ;
    PORT
      LAYER met2 ;
        RECT 93.470 499.200 93.750 501.500 ;
    END
  END FrameData_O[7]
  PIN FrameData_O[8]
    DIRECTION OUTPUT ;
    USE SIGNAL ;
    ANTENNADIFFAREA 0.445500 ;
    PORT
      LAYER met2 ;
        RECT 122.450 499.200 122.730 501.500 ;
    END
  END FrameData_O[8]
  PIN FrameData_O[9]
    DIRECTION OUTPUT ;
    USE SIGNAL ;
    ANTENNADIFFAREA 0.445500 ;
    PORT
      LAYER met2 ;
        RECT 58.050 499.200 58.330 501.500 ;
    END
  END FrameData_O[9]
  PIN FrameStrobe[0]
    DIRECTION INPUT ;
    USE SIGNAL ;
    ANTENNAGATEAREA 0.196500 ;
    PORT
      LAYER met3 ;
        RECT -1.500 64.640 0.800 65.240 ;
    END
  END FrameStrobe[0]
  PIN FrameStrobe[10]
    DIRECTION INPUT ;
    USE SIGNAL ;
    ANTENNAGATEAREA 0.213000 ;
    PORT
      LAYER met2 ;
        RECT 338.190 499.200 338.470 501.500 ;
    END
  END FrameStrobe[10]
  PIN FrameStrobe[11]
    DIRECTION INPUT ;
    USE SIGNAL ;
    ANTENNAGATEAREA 0.196500 ;
    PORT
      LAYER met2 ;
        RECT 128.890 499.200 129.170 501.500 ;
    END
  END FrameStrobe[11]
  PIN FrameStrobe[12]
    DIRECTION INPUT ;
    USE SIGNAL ;
    ANTENNAGATEAREA 0.196500 ;
    PORT
      LAYER met2 ;
        RECT 154.650 499.200 154.930 501.500 ;
    END
  END FrameStrobe[12]
  PIN FrameStrobe[13]
    DIRECTION INPUT ;
    USE SIGNAL ;
    ANTENNAGATEAREA 0.126000 ;
    PORT
      LAYER met2 ;
        RECT 334.970 499.200 335.250 501.500 ;
    END
  END FrameStrobe[13]
  PIN FrameStrobe[14]
    DIRECTION INPUT ;
    USE SIGNAL ;
    ANTENNAGATEAREA 0.196500 ;
    PORT
      LAYER met2 ;
        RECT 370.390 499.200 370.670 501.500 ;
    END
  END FrameStrobe[14]
  PIN FrameStrobe[15]
    DIRECTION INPUT ;
    USE SIGNAL ;
    ANTENNAGATEAREA 0.213000 ;
    PORT
      LAYER met2 ;
        RECT 412.250 499.200 412.530 501.500 ;
    END
  END FrameStrobe[15]
  PIN FrameStrobe[16]
    DIRECTION INPUT ;
    USE SIGNAL ;
    ANTENNAGATEAREA 0.196500 ;
    PORT
      LAYER met2 ;
        RECT 399.370 499.200 399.650 501.500 ;
    END
  END FrameStrobe[16]
  PIN FrameStrobe[17]
    DIRECTION INPUT ;
    USE SIGNAL ;
    ANTENNAGATEAREA 0.126000 ;
    PORT
      LAYER met2 ;
        RECT 396.150 499.200 396.430 501.500 ;
    END
  END FrameStrobe[17]
  PIN FrameStrobe[18]
    DIRECTION INPUT ;
    USE SIGNAL ;
    ANTENNAGATEAREA 0.213000 ;
    PORT
      LAYER met2 ;
        RECT 392.930 499.200 393.210 501.500 ;
    END
  END FrameStrobe[18]
  PIN FrameStrobe[19]
    DIRECTION INPUT ;
    USE SIGNAL ;
    ANTENNAGATEAREA 0.196500 ;
    PORT
      LAYER met3 ;
        RECT -1.500 68.040 0.800 68.640 ;
    END
  END FrameStrobe[19]
  PIN FrameStrobe[1]
    DIRECTION INPUT ;
    USE SIGNAL ;
    ANTENNAGATEAREA 0.159000 ;
    PORT
      LAYER met3 ;
        RECT -1.500 81.640 0.800 82.240 ;
    END
  END FrameStrobe[1]
  PIN FrameStrobe[2]
    DIRECTION INPUT ;
    USE SIGNAL ;
    ANTENNAGATEAREA 0.196500 ;
    PORT
      LAYER met3 ;
        RECT -1.500 44.240 0.800 44.840 ;
    END
  END FrameStrobe[2]
  PIN FrameStrobe[3]
    DIRECTION INPUT ;
    USE SIGNAL ;
    ANTENNAGATEAREA 0.196500 ;
    PORT
      LAYER met3 ;
        RECT -1.500 98.640 0.800 99.240 ;
    END
  END FrameStrobe[3]
  PIN FrameStrobe[4]
    DIRECTION INPUT ;
    USE SIGNAL ;
    ANTENNAGATEAREA 0.196500 ;
    PORT
      LAYER met3 ;
        RECT -1.500 51.040 0.800 51.640 ;
    END
  END FrameStrobe[4]
  PIN FrameStrobe[5]
    DIRECTION INPUT ;
    USE SIGNAL ;
    ANTENNAGATEAREA 0.213000 ;
    PORT
      LAYER met3 ;
        RECT -1.500 112.240 0.800 112.840 ;
    END
  END FrameStrobe[5]
  PIN FrameStrobe[6]
    DIRECTION INPUT ;
    USE SIGNAL ;
    ANTENNAGATEAREA 0.213000 ;
    PORT
      LAYER met3 ;
        RECT -1.500 391.040 0.800 391.640 ;
    END
  END FrameStrobe[6]
  PIN FrameStrobe[7]
    DIRECTION INPUT ;
    USE SIGNAL ;
    ANTENNAGATEAREA 0.196500 ;
    PORT
      LAYER met3 ;
        RECT -1.500 370.640 0.800 371.240 ;
    END
  END FrameStrobe[7]
  PIN FrameStrobe[8]
    DIRECTION INPUT ;
    USE SIGNAL ;
    ANTENNAGATEAREA 0.159000 ;
    PORT
      LAYER met2 ;
        RECT 409.030 499.200 409.310 501.500 ;
    END
  END FrameStrobe[8]
  PIN FrameStrobe[9]
    DIRECTION INPUT ;
    USE SIGNAL ;
    ANTENNAGATEAREA 0.196500 ;
    PORT
      LAYER met3 ;
        RECT -1.500 377.440 0.800 378.040 ;
    END
  END FrameStrobe[9]
  PIN FrameStrobe_O[0]
    DIRECTION OUTPUT ;
    USE SIGNAL ;
    ANTENNADIFFAREA 0.445500 ;
    PORT
      LAYER met3 ;
        RECT -1.500 54.440 0.800 55.040 ;
    END
  END FrameStrobe_O[0]
  PIN FrameStrobe_O[10]
    DIRECTION OUTPUT ;
    USE SIGNAL ;
    ANTENNADIFFAREA 0.445500 ;
    PORT
      LAYER met2 ;
        RECT 106.350 499.200 106.630 501.500 ;
    END
  END FrameStrobe_O[10]
  PIN FrameStrobe_O[11]
    DIRECTION OUTPUT ;
    USE SIGNAL ;
    ANTENNADIFFAREA 0.445500 ;
    PORT
      LAYER met2 ;
        RECT 132.110 499.200 132.390 501.500 ;
    END
  END FrameStrobe_O[11]
  PIN FrameStrobe_O[12]
    DIRECTION OUTPUT ;
    USE SIGNAL ;
    ANTENNADIFFAREA 0.445500 ;
    PORT
      LAYER met2 ;
        RECT 180.410 499.200 180.690 501.500 ;
    END
  END FrameStrobe_O[12]
  PIN FrameStrobe_O[13]
    DIRECTION OUTPUT ;
    USE SIGNAL ;
    ANTENNADIFFAREA 0.445500 ;
    PORT
      LAYER met2 ;
        RECT 193.290 499.200 193.570 501.500 ;
    END
  END FrameStrobe_O[13]
  PIN FrameStrobe_O[14]
    DIRECTION OUTPUT ;
    USE SIGNAL ;
    ANTENNADIFFAREA 0.445500 ;
    PORT
      LAYER met2 ;
        RECT 367.170 499.200 367.450 501.500 ;
    END
  END FrameStrobe_O[14]
  PIN FrameStrobe_O[15]
    DIRECTION OUTPUT ;
    USE SIGNAL ;
    ANTENNADIFFAREA 0.445500 ;
    PORT
      LAYER met2 ;
        RECT 405.810 499.200 406.090 501.500 ;
    END
  END FrameStrobe_O[15]
  PIN FrameStrobe_O[16]
    DIRECTION OUTPUT ;
    USE SIGNAL ;
    ANTENNADIFFAREA 0.445500 ;
    PORT
      LAYER met2 ;
        RECT 389.710 499.200 389.990 501.500 ;
    END
  END FrameStrobe_O[16]
  PIN FrameStrobe_O[17]
    DIRECTION OUTPUT ;
    USE SIGNAL ;
    ANTENNADIFFAREA 0.445500 ;
    PORT
      LAYER met2 ;
        RECT 386.490 499.200 386.770 501.500 ;
    END
  END FrameStrobe_O[17]
  PIN FrameStrobe_O[18]
    DIRECTION OUTPUT ;
    USE SIGNAL ;
    ANTENNADIFFAREA 0.445500 ;
    PORT
      LAYER met2 ;
        RECT 383.270 499.200 383.550 501.500 ;
    END
  END FrameStrobe_O[18]
  PIN FrameStrobe_O[19]
    DIRECTION OUTPUT ;
    USE SIGNAL ;
    ANTENNADIFFAREA 0.445500 ;
    PORT
      LAYER met3 ;
        RECT -1.500 88.440 0.800 89.040 ;
    END
  END FrameStrobe_O[19]
  PIN FrameStrobe_O[1]
    DIRECTION OUTPUT ;
    USE SIGNAL ;
    ANTENNADIFFAREA 0.445500 ;
    PORT
      LAYER met3 ;
        RECT -1.500 74.840 0.800 75.440 ;
    END
  END FrameStrobe_O[1]
  PIN FrameStrobe_O[2]
    DIRECTION OUTPUT ;
    USE SIGNAL ;
    ANTENNADIFFAREA 0.445500 ;
    PORT
      LAYER met3 ;
        RECT -1.500 85.040 0.800 85.640 ;
    END
  END FrameStrobe_O[2]
  PIN FrameStrobe_O[3]
    DIRECTION OUTPUT ;
    USE SIGNAL ;
    ANTENNADIFFAREA 0.445500 ;
    PORT
      LAYER met3 ;
        RECT -1.500 108.840 0.800 109.440 ;
    END
  END FrameStrobe_O[3]
  PIN FrameStrobe_O[4]
    DIRECTION OUTPUT ;
    USE SIGNAL ;
    ANTENNADIFFAREA 0.445500 ;
    PORT
      LAYER met3 ;
        RECT -1.500 78.240 0.800 78.840 ;
    END
  END FrameStrobe_O[4]
  PIN FrameStrobe_O[5]
    DIRECTION OUTPUT ;
    USE SIGNAL ;
    ANTENNADIFFAREA 0.445500 ;
    PORT
      LAYER met3 ;
        RECT -1.500 125.840 0.800 126.440 ;
    END
  END FrameStrobe_O[5]
  PIN FrameStrobe_O[6]
    DIRECTION OUTPUT ;
    USE SIGNAL ;
    ANTENNADIFFAREA 0.445500 ;
    PORT
      LAYER met3 ;
        RECT -1.500 132.640 0.800 133.240 ;
    END
  END FrameStrobe_O[6]
  PIN FrameStrobe_O[7]
    DIRECTION OUTPUT ;
    USE SIGNAL ;
    ANTENNADIFFAREA 0.445500 ;
    PORT
      LAYER met3 ;
        RECT -1.500 360.440 0.800 361.040 ;
    END
  END FrameStrobe_O[7]
  PIN FrameStrobe_O[8]
    DIRECTION OUTPUT ;
    USE SIGNAL ;
    ANTENNADIFFAREA 0.445500 ;
    PORT
      LAYER met2 ;
        RECT 138.550 499.200 138.830 501.500 ;
    END
  END FrameStrobe_O[8]
  PIN FrameStrobe_O[9]
    DIRECTION OUTPUT ;
    USE SIGNAL ;
    ANTENNADIFFAREA 0.445500 ;
    PORT
      LAYER met2 ;
        RECT 99.910 499.200 100.190 501.500 ;
    END
  END FrameStrobe_O[9]
  PIN N1BEG[0]
    DIRECTION OUTPUT ;
    USE SIGNAL ;
    ANTENNADIFFAREA 0.795200 ;
    PORT
      LAYER met3 ;
        RECT 499.200 231.240 501.500 231.840 ;
    END
  END N1BEG[0]
  PIN N1BEG[1]
    DIRECTION OUTPUT ;
    USE SIGNAL ;
    ANTENNADIFFAREA 0.445500 ;
    PORT
      LAYER met2 ;
        RECT 238.370 -1.500 238.650 0.800 ;
    END
  END N1BEG[1]
  PIN N1BEG[2]
    DIRECTION OUTPUT ;
    USE SIGNAL ;
    ANTENNADIFFAREA 1.336500 ;
    PORT
      LAYER met3 ;
        RECT -1.500 350.240 0.800 350.840 ;
    END
  END N1BEG[2]
  PIN N1BEG[3]
    DIRECTION OUTPUT ;
    USE SIGNAL ;
    ANTENNADIFFAREA 1.782000 ;
    PORT
      LAYER met2 ;
        RECT 144.990 499.200 145.270 501.500 ;
    END
  END N1BEG[3]
  PIN N1END[0]
    DIRECTION INPUT ;
    USE SIGNAL ;
    ANTENNAGATEAREA 0.213000 ;
    PORT
      LAYER met3 ;
        RECT -1.500 146.240 0.800 146.840 ;
    END
  END N1END[0]
  PIN N1END[1]
    DIRECTION INPUT ;
    USE SIGNAL ;
    ANTENNAGATEAREA 0.426000 ;
    PORT
      LAYER met2 ;
        RECT 144.990 -1.500 145.270 0.800 ;
    END
  END N1END[1]
  PIN N1END[2]
    DIRECTION INPUT ;
    USE SIGNAL ;
    ANTENNAGATEAREA 0.426000 ;
    PORT
      LAYER met3 ;
        RECT -1.500 71.440 0.800 72.040 ;
    END
  END N1END[2]
  PIN N1END[3]
    DIRECTION INPUT ;
    USE SIGNAL ;
    ANTENNAGATEAREA 0.247500 ;
    PORT
      LAYER met2 ;
        RECT 376.830 -1.500 377.110 0.800 ;
    END
  END N1END[3]
  PIN N2BEG[0]
    DIRECTION OUTPUT ;
    USE SIGNAL ;
    ANTENNADIFFAREA 1.336500 ;
    PORT
      LAYER met2 ;
        RECT 244.810 -1.500 245.090 0.800 ;
    END
  END N2BEG[0]
  PIN N2BEG[1]
    DIRECTION OUTPUT ;
    USE SIGNAL ;
    ANTENNADIFFAREA 1.782000 ;
    PORT
      LAYER met3 ;
        RECT -1.500 357.040 0.800 357.640 ;
    END
  END N2BEG[1]
  PIN N2BEG[2]
    DIRECTION OUTPUT ;
    USE SIGNAL ;
    ANTENNADIFFAREA 1.336500 ;
    PORT
      LAYER met3 ;
        RECT -1.500 326.440 0.800 327.040 ;
    END
  END N2BEG[2]
  PIN N2BEG[3]
    DIRECTION OUTPUT ;
    USE SIGNAL ;
    ANTENNADIFFAREA 1.782000 ;
    PORT
      LAYER met3 ;
        RECT -1.500 292.440 0.800 293.040 ;
    END
  END N2BEG[3]
  PIN N2BEG[4]
    DIRECTION OUTPUT ;
    USE SIGNAL ;
    ANTENNADIFFAREA 1.336500 ;
    PORT
      LAYER met2 ;
        RECT 219.050 -1.500 219.330 0.800 ;
    END
  END N2BEG[4]
  PIN N2BEG[5]
    DIRECTION OUTPUT ;
    USE SIGNAL ;
    ANTENNADIFFAREA 1.782000 ;
    PORT
      LAYER met2 ;
        RECT 219.050 499.200 219.330 501.500 ;
    END
  END N2BEG[5]
  PIN N2BEG[6]
    DIRECTION OUTPUT ;
    USE SIGNAL ;
    ANTENNADIFFAREA 1.336500 ;
    PORT
      LAYER met2 ;
        RECT 296.330 -1.500 296.610 0.800 ;
    END
  END N2BEG[6]
  PIN N2BEG[7]
    DIRECTION OUTPUT ;
    USE SIGNAL ;
    ANTENNADIFFAREA 1.782000 ;
    PORT
      LAYER met3 ;
        RECT -1.500 156.440 0.800 157.040 ;
    END
  END N2BEG[7]
  PIN N2BEGb[0]
    DIRECTION OUTPUT ;
    USE SIGNAL ;
    ANTENNADIFFAREA 0.445500 ;
    PORT
      LAYER met2 ;
        RECT 270.570 499.200 270.850 501.500 ;
    END
  END N2BEGb[0]
  PIN N2BEGb[1]
    DIRECTION OUTPUT ;
    USE SIGNAL ;
    ANTENNADIFFAREA 0.445500 ;
    PORT
      LAYER met2 ;
        RECT 289.890 499.200 290.170 501.500 ;
    END
  END N2BEGb[1]
  PIN N2BEGb[2]
    DIRECTION OUTPUT ;
    USE SIGNAL ;
    ANTENNADIFFAREA 0.445500 ;
    PORT
      LAYER met3 ;
        RECT 499.200 74.840 501.500 75.440 ;
    END
  END N2BEGb[2]
  PIN N2BEGb[3]
    DIRECTION OUTPUT ;
    USE SIGNAL ;
    ANTENNADIFFAREA 0.445500 ;
    PORT
      LAYER met3 ;
        RECT 499.200 44.240 501.500 44.840 ;
    END
  END N2BEGb[3]
  PIN N2BEGb[4]
    DIRECTION OUTPUT ;
    USE SIGNAL ;
    ANTENNADIFFAREA 0.445500 ;
    PORT
      LAYER met2 ;
        RECT 289.890 -1.500 290.170 0.800 ;
    END
  END N2BEGb[4]
  PIN N2BEGb[5]
    DIRECTION OUTPUT ;
    USE SIGNAL ;
    ANTENNADIFFAREA 0.445500 ;
    PORT
      LAYER met3 ;
        RECT 499.200 95.240 501.500 95.840 ;
    END
  END N2BEGb[5]
  PIN N2BEGb[6]
    DIRECTION OUTPUT ;
    USE SIGNAL ;
    ANTENNADIFFAREA 0.445500 ;
    PORT
      LAYER met2 ;
        RECT 241.590 499.200 241.870 501.500 ;
    END
  END N2BEGb[6]
  PIN N2BEGb[7]
    DIRECTION OUTPUT ;
    USE SIGNAL ;
    ANTENNADIFFAREA 0.445500 ;
    PORT
      LAYER met2 ;
        RECT 148.210 499.200 148.490 501.500 ;
    END
  END N2BEGb[7]
  PIN N2END[0]
    DIRECTION INPUT ;
    USE SIGNAL ;
    ANTENNAGATEAREA 0.159000 ;
    PORT
      LAYER met3 ;
        RECT -1.500 139.440 0.800 140.040 ;
    END
  END N2END[0]
  PIN N2END[1]
    DIRECTION INPUT ;
    USE SIGNAL ;
    ANTENNAGATEAREA 0.159000 ;
    PORT
      LAYER met2 ;
        RECT 180.410 -1.500 180.690 0.800 ;
    END
  END N2END[1]
  PIN N2END[2]
    DIRECTION INPUT ;
    USE SIGNAL ;
    ANTENNAGATEAREA 0.213000 ;
    PORT
      LAYER met3 ;
        RECT -1.500 272.040 0.800 272.640 ;
    END
  END N2END[2]
  PIN N2END[3]
    DIRECTION INPUT ;
    USE SIGNAL ;
    ANTENNAGATEAREA 0.159000 ;
    PORT
      LAYER met3 ;
        RECT -1.500 268.640 0.800 269.240 ;
    END
  END N2END[3]
  PIN N2END[4]
    DIRECTION INPUT ;
    USE SIGNAL ;
    ANTENNAGATEAREA 0.159000 ;
    PORT
      LAYER met3 ;
        RECT -1.500 224.440 0.800 225.040 ;
    END
  END N2END[4]
  PIN N2END[5]
    DIRECTION INPUT ;
    USE SIGNAL ;
    ANTENNAGATEAREA 0.213000 ;
    PORT
      LAYER met2 ;
        RECT 318.870 -1.500 319.150 0.800 ;
    END
  END N2END[5]
  PIN N2END[6]
    DIRECTION INPUT ;
    USE SIGNAL ;
    ANTENNAGATEAREA 0.159000 ;
    PORT
      LAYER met3 ;
        RECT -1.500 47.640 0.800 48.240 ;
    END
  END N2END[6]
  PIN N2END[7]
    DIRECTION INPUT ;
    USE SIGNAL ;
    ANTENNAGATEAREA 0.159000 ;
    PORT
      LAYER met2 ;
        RECT 334.970 -1.500 335.250 0.800 ;
    END
  END N2END[7]
  PIN N2MID[0]
    DIRECTION INPUT ;
    USE SIGNAL ;
    ANTENNAGATEAREA 0.213000 ;
    PORT
      LAYER met2 ;
        RECT 267.350 499.200 267.630 501.500 ;
    END
  END N2MID[0]
  PIN N2MID[1]
    DIRECTION INPUT ;
    USE SIGNAL ;
    ANTENNAGATEAREA 0.196500 ;
    PORT
      LAYER met2 ;
        RECT 257.690 499.200 257.970 501.500 ;
    END
  END N2MID[1]
  PIN N2MID[2]
    DIRECTION INPUT ;
    USE SIGNAL ;
    ANTENNAGATEAREA 0.213000 ;
    PORT
      LAYER met3 ;
        RECT 499.200 61.240 501.500 61.840 ;
    END
  END N2MID[2]
  PIN N2MID[3]
    DIRECTION INPUT ;
    USE SIGNAL ;
    ANTENNAGATEAREA 0.213000 ;
    PORT
      LAYER met3 ;
        RECT 499.200 261.840 501.500 262.440 ;
    END
  END N2MID[3]
  PIN N2MID[4]
    DIRECTION INPUT ;
    USE SIGNAL ;
    ANTENNAGATEAREA 0.213000 ;
    PORT
      LAYER met2 ;
        RECT 283.450 -1.500 283.730 0.800 ;
    END
  END N2MID[4]
  PIN N2MID[5]
    DIRECTION INPUT ;
    USE SIGNAL ;
    ANTENNAGATEAREA 0.159000 ;
    PORT
      LAYER met3 ;
        RECT 499.200 129.240 501.500 129.840 ;
    END
  END N2MID[5]
  PIN N2MID[6]
    DIRECTION INPUT ;
    USE SIGNAL ;
    ANTENNAGATEAREA 0.213000 ;
    PORT
      LAYER met2 ;
        RECT 248.030 499.200 248.310 501.500 ;
    END
  END N2MID[6]
  PIN N2MID[7]
    DIRECTION INPUT ;
    USE SIGNAL ;
    ANTENNAGATEAREA 0.213000 ;
    PORT
      LAYER met2 ;
        RECT 103.130 499.200 103.410 501.500 ;
    END
  END N2MID[7]
  PIN N4BEG[0]
    DIRECTION OUTPUT ;
    USE SIGNAL ;
    ANTENNADIFFAREA 0.445500 ;
    PORT
      LAYER met3 ;
        RECT 499.200 353.640 501.500 354.240 ;
    END
  END N4BEG[0]
  PIN N4BEG[10]
    DIRECTION OUTPUT ;
    USE SIGNAL ;
    ANTENNADIFFAREA 0.445500 ;
    PORT
      LAYER met3 ;
        RECT 499.200 333.240 501.500 333.840 ;
    END
  END N4BEG[10]
  PIN N4BEG[11]
    DIRECTION OUTPUT ;
    USE SIGNAL ;
    ANTENNADIFFAREA 0.445500 ;
    PORT
      LAYER met3 ;
        RECT 499.200 173.440 501.500 174.040 ;
    END
  END N4BEG[11]
  PIN N4BEG[12]
    DIRECTION OUTPUT ;
    USE SIGNAL ;
    ANTENNADIFFAREA 1.782000 ;
    PORT
      LAYER met3 ;
        RECT -1.500 255.040 0.800 255.640 ;
    END
  END N4BEG[12]
  PIN N4BEG[13]
    DIRECTION OUTPUT ;
    USE SIGNAL ;
    ANTENNADIFFAREA 0.445500 ;
    PORT
      LAYER met3 ;
        RECT -1.500 265.240 0.800 265.840 ;
    END
  END N4BEG[13]
  PIN N4BEG[14]
    DIRECTION OUTPUT ;
    USE SIGNAL ;
    ANTENNADIFFAREA 1.336500 ;
    PORT
      LAYER met3 ;
        RECT -1.500 210.840 0.800 211.440 ;
    END
  END N4BEG[14]
  PIN N4BEG[15]
    DIRECTION OUTPUT ;
    USE SIGNAL ;
    ANTENNADIFFAREA 1.336500 ;
    PORT
      LAYER met3 ;
        RECT -1.500 214.240 0.800 214.840 ;
    END
  END N4BEG[15]
  PIN N4BEG[1]
    DIRECTION OUTPUT ;
    USE SIGNAL ;
    ANTENNADIFFAREA 0.445500 ;
    PORT
      LAYER met2 ;
        RECT 325.310 499.200 325.590 501.500 ;
    END
  END N4BEG[1]
  PIN N4BEG[2]
    DIRECTION OUTPUT ;
    USE SIGNAL ;
    ANTENNADIFFAREA 0.445500 ;
    PORT
      LAYER met2 ;
        RECT 434.790 -1.500 435.070 0.800 ;
    END
  END N4BEG[2]
  PIN N4BEG[3]
    DIRECTION OUTPUT ;
    USE SIGNAL ;
    ANTENNADIFFAREA 0.445500 ;
    PORT
      LAYER met3 ;
        RECT 499.200 336.640 501.500 337.240 ;
    END
  END N4BEG[3]
  PIN N4BEG[4]
    DIRECTION OUTPUT ;
    USE SIGNAL ;
    ANTENNADIFFAREA 0.445500 ;
    PORT
      LAYER met3 ;
        RECT 499.200 397.840 501.500 398.440 ;
    END
  END N4BEG[4]
  PIN N4BEG[5]
    DIRECTION OUTPUT ;
    USE SIGNAL ;
    ANTENNADIFFAREA 0.445500 ;
    PORT
      LAYER met3 ;
        RECT 499.200 17.040 501.500 17.640 ;
    END
  END N4BEG[5]
  PIN N4BEG[6]
    DIRECTION OUTPUT ;
    USE SIGNAL ;
    ANTENNADIFFAREA 0.445500 ;
    PORT
      LAYER met3 ;
        RECT 499.200 462.440 501.500 463.040 ;
    END
  END N4BEG[6]
  PIN N4BEG[7]
    DIRECTION OUTPUT ;
    USE SIGNAL ;
    ANTENNADIFFAREA 0.445500 ;
    PORT
      LAYER met2 ;
        RECT 418.690 -1.500 418.970 0.800 ;
    END
  END N4BEG[7]
  PIN N4BEG[8]
    DIRECTION OUTPUT ;
    USE SIGNAL ;
    ANTENNADIFFAREA 0.445500 ;
    PORT
      LAYER met2 ;
        RECT 473.430 -1.500 473.710 0.800 ;
    END
  END N4BEG[8]
  PIN N4BEG[9]
    DIRECTION OUTPUT ;
    USE SIGNAL ;
    ANTENNADIFFAREA 0.445500 ;
    PORT
      LAYER met3 ;
        RECT 499.200 210.840 501.500 211.440 ;
    END
  END N4BEG[9]
  PIN N4END[0]
    DIRECTION INPUT ;
    USE SIGNAL ;
    ANTENNAGATEAREA 0.213000 ;
    PORT
      LAYER met3 ;
        RECT -1.500 367.240 0.800 367.840 ;
    END
  END N4END[0]
  PIN N4END[10]
    DIRECTION INPUT ;
    USE SIGNAL ;
    ANTENNAGATEAREA 0.196500 ;
    PORT
      LAYER met3 ;
        RECT 499.200 465.840 501.500 466.440 ;
    END
  END N4END[10]
  PIN N4END[11]
    DIRECTION INPUT ;
    USE SIGNAL ;
    ANTENNAGATEAREA 0.196500 ;
    PORT
      LAYER met2 ;
        RECT 447.670 -1.500 447.950 0.800 ;
    END
  END N4END[11]
  PIN N4END[12]
    DIRECTION INPUT ;
    USE SIGNAL ;
    ANTENNAGATEAREA 0.196500 ;
    PORT
      LAYER met2 ;
        RECT 492.750 -1.500 493.030 0.800 ;
    END
  END N4END[12]
  PIN N4END[13]
    DIRECTION INPUT ;
    USE SIGNAL ;
    ANTENNAGATEAREA 0.196500 ;
    PORT
      LAYER met3 ;
        RECT 499.200 207.440 501.500 208.040 ;
    END
  END N4END[13]
  PIN N4END[14]
    DIRECTION INPUT ;
    USE SIGNAL ;
    ANTENNAGATEAREA 0.196500 ;
    PORT
      LAYER met3 ;
        RECT 499.200 455.640 501.500 456.240 ;
    END
  END N4END[14]
  PIN N4END[15]
    DIRECTION INPUT ;
    USE SIGNAL ;
    ANTENNAGATEAREA 0.196500 ;
    PORT
      LAYER met3 ;
        RECT 499.200 193.840 501.500 194.440 ;
    END
  END N4END[15]
  PIN N4END[1]
    DIRECTION INPUT ;
    USE SIGNAL ;
    ANTENNAGATEAREA 0.159000 ;
    PORT
      LAYER met2 ;
        RECT 193.290 -1.500 193.570 0.800 ;
    END
  END N4END[1]
  PIN N4END[2]
    DIRECTION INPUT ;
    USE SIGNAL ;
    ANTENNAGATEAREA 0.159000 ;
    PORT
      LAYER met3 ;
        RECT -1.500 248.240 0.800 248.840 ;
    END
  END N4END[2]
  PIN N4END[3]
    DIRECTION INPUT ;
    USE SIGNAL ;
    ANTENNAGATEAREA 0.159000 ;
    PORT
      LAYER met3 ;
        RECT -1.500 241.440 0.800 242.040 ;
    END
  END N4END[3]
  PIN N4END[4]
    DIRECTION INPUT ;
    USE SIGNAL ;
    ANTENNAGATEAREA 0.196500 ;
    PORT
      LAYER met3 ;
        RECT 499.200 448.840 501.500 449.440 ;
    END
  END N4END[4]
  PIN N4END[5]
    DIRECTION INPUT ;
    USE SIGNAL ;
    ANTENNAGATEAREA 0.196500 ;
    PORT
      LAYER met2 ;
        RECT 328.530 499.200 328.810 501.500 ;
    END
  END N4END[5]
  PIN N4END[6]
    DIRECTION INPUT ;
    USE SIGNAL ;
    ANTENNAGATEAREA 0.196500 ;
    PORT
      LAYER met2 ;
        RECT 425.130 -1.500 425.410 0.800 ;
    END
  END N4END[6]
  PIN N4END[7]
    DIRECTION INPUT ;
    USE SIGNAL ;
    ANTENNAGATEAREA 0.196500 ;
    PORT
      LAYER met3 ;
        RECT 499.200 343.440 501.500 344.040 ;
    END
  END N4END[7]
  PIN N4END[8]
    DIRECTION INPUT ;
    USE SIGNAL ;
    ANTENNAGATEAREA 0.196500 ;
    PORT
      LAYER met3 ;
        RECT 499.200 414.840 501.500 415.440 ;
    END
  END N4END[8]
  PIN N4END[9]
    DIRECTION INPUT ;
    USE SIGNAL ;
    ANTENNAGATEAREA 0.196500 ;
    PORT
      LAYER met3 ;
        RECT 499.200 13.640 501.500 14.240 ;
    END
  END N4END[9]
  PIN NN4BEG[0]
    DIRECTION OUTPUT ;
    USE SIGNAL ;
    ANTENNADIFFAREA 0.445500 ;
    PORT
      LAYER met3 ;
        RECT 499.200 81.640 501.500 82.240 ;
    END
  END NN4BEG[0]
  PIN NN4BEG[10]
    DIRECTION OUTPUT ;
    USE SIGNAL ;
    ANTENNADIFFAREA 0.445500 ;
    PORT
      LAYER met3 ;
        RECT 499.200 435.240 501.500 435.840 ;
    END
  END NN4BEG[10]
  PIN NN4BEG[11]
    DIRECTION OUTPUT ;
    USE SIGNAL ;
    ANTENNADIFFAREA 0.445500 ;
    PORT
      LAYER met2 ;
        RECT 357.510 -1.500 357.790 0.800 ;
    END
  END NN4BEG[11]
  PIN NN4BEG[12]
    DIRECTION OUTPUT ;
    USE SIGNAL ;
    ANTENNADIFFAREA 1.336500 ;
    PORT
      LAYER met2 ;
        RECT 225.490 -1.500 225.770 0.800 ;
    END
  END NN4BEG[12]
  PIN NN4BEG[13]
    DIRECTION OUTPUT ;
    USE SIGNAL ;
    ANTENNADIFFAREA 1.782000 ;
    PORT
      LAYER met3 ;
        RECT 499.200 132.640 501.500 133.240 ;
    END
  END NN4BEG[13]
  PIN NN4BEG[14]
    DIRECTION OUTPUT ;
    USE SIGNAL ;
    ANTENNADIFFAREA 1.782000 ;
    PORT
      LAYER met2 ;
        RECT 173.970 -1.500 174.250 0.800 ;
    END
  END NN4BEG[14]
  PIN NN4BEG[15]
    DIRECTION OUTPUT ;
    USE SIGNAL ;
    ANTENNADIFFAREA 1.782000 ;
    PORT
      LAYER met3 ;
        RECT 499.200 204.040 501.500 204.640 ;
    END
  END NN4BEG[15]
  PIN NN4BEG[1]
    DIRECTION OUTPUT ;
    USE SIGNAL ;
    ANTENNADIFFAREA 0.445500 ;
    PORT
      LAYER met3 ;
        RECT 499.200 159.840 501.500 160.440 ;
    END
  END NN4BEG[1]
  PIN NN4BEG[2]
    DIRECTION OUTPUT ;
    USE SIGNAL ;
    ANTENNADIFFAREA 0.445500 ;
    PORT
      LAYER met3 ;
        RECT 499.200 360.440 501.500 361.040 ;
    END
  END NN4BEG[2]
  PIN NN4BEG[3]
    DIRECTION OUTPUT ;
    USE SIGNAL ;
    ANTENNADIFFAREA 0.445500 ;
    PORT
      LAYER met3 ;
        RECT -1.500 493.040 0.800 493.640 ;
    END
  END NN4BEG[3]
  PIN NN4BEG[4]
    DIRECTION OUTPUT ;
    USE SIGNAL ;
    ANTENNADIFFAREA 0.445500 ;
    PORT
      LAYER met3 ;
        RECT 499.200 486.240 501.500 486.840 ;
    END
  END NN4BEG[4]
  PIN NN4BEG[5]
    DIRECTION OUTPUT ;
    USE SIGNAL ;
    ANTENNADIFFAREA 0.445500 ;
    PORT
      LAYER met3 ;
        RECT 499.200 275.440 501.500 276.040 ;
    END
  END NN4BEG[5]
  PIN NN4BEG[6]
    DIRECTION OUTPUT ;
    USE SIGNAL ;
    ANTENNADIFFAREA 0.445500 ;
    PORT
      LAYER met3 ;
        RECT 499.200 329.840 501.500 330.440 ;
    END
  END NN4BEG[6]
  PIN NN4BEG[7]
    DIRECTION OUTPUT ;
    USE SIGNAL ;
    ANTENNADIFFAREA 0.445500 ;
    PORT
      LAYER met2 ;
        RECT 479.870 -1.500 480.150 0.800 ;
    END
  END NN4BEG[7]
  PIN NN4BEG[8]
    DIRECTION OUTPUT ;
    USE SIGNAL ;
    ANTENNADIFFAREA 0.445500 ;
    PORT
      LAYER met3 ;
        RECT -1.500 482.840 0.800 483.440 ;
    END
  END NN4BEG[8]
  PIN NN4BEG[9]
    DIRECTION OUTPUT ;
    USE SIGNAL ;
    ANTENNADIFFAREA 0.445500 ;
    PORT
      LAYER met3 ;
        RECT 499.200 346.840 501.500 347.440 ;
    END
  END NN4BEG[9]
  PIN NN4END[0]
    DIRECTION INPUT ;
    USE SIGNAL ;
    ANTENNAGATEAREA 0.213000 ;
    PORT
      LAYER met3 ;
        RECT -1.500 166.640 0.800 167.240 ;
    END
  END NN4END[0]
  PIN NN4END[10]
    DIRECTION INPUT ;
    USE SIGNAL ;
    ANTENNAGATEAREA 0.196500 ;
    PORT
      LAYER met3 ;
        RECT 499.200 374.040 501.500 374.640 ;
    END
  END NN4END[10]
  PIN NN4END[11]
    DIRECTION INPUT ;
    USE SIGNAL ;
    ANTENNAGATEAREA 0.196500 ;
    PORT
      LAYER met2 ;
        RECT 470.210 -1.500 470.490 0.800 ;
    END
  END NN4END[11]
  PIN NN4END[12]
    DIRECTION INPUT ;
    USE SIGNAL ;
    ANTENNAGATEAREA 0.196500 ;
    PORT
      LAYER met3 ;
        RECT -1.500 472.640 0.800 473.240 ;
    END
  END NN4END[12]
  PIN NN4END[13]
    DIRECTION INPUT ;
    USE SIGNAL ;
    ANTENNAGATEAREA 0.196500 ;
    PORT
      LAYER met3 ;
        RECT 499.200 340.040 501.500 340.640 ;
    END
  END NN4END[13]
  PIN NN4END[14]
    DIRECTION INPUT ;
    USE SIGNAL ;
    ANTENNAGATEAREA 0.196500 ;
    PORT
      LAYER met3 ;
        RECT 499.200 438.640 501.500 439.240 ;
    END
  END NN4END[14]
  PIN NN4END[15]
    DIRECTION INPUT ;
    USE SIGNAL ;
    ANTENNAGATEAREA 0.196500 ;
    PORT
      LAYER met2 ;
        RECT 351.070 -1.500 351.350 0.800 ;
    END
  END NN4END[15]
  PIN NN4END[1]
    DIRECTION INPUT ;
    USE SIGNAL ;
    ANTENNAGATEAREA 0.159000 ;
    PORT
      LAYER met2 ;
        RECT 177.190 -1.500 177.470 0.800 ;
    END
  END NN4END[1]
  PIN NN4END[2]
    DIRECTION INPUT ;
    USE SIGNAL ;
    ANTENNAGATEAREA 0.159000 ;
    PORT
      LAYER met3 ;
        RECT -1.500 173.440 0.800 174.040 ;
    END
  END NN4END[2]
  PIN NN4END[3]
    DIRECTION INPUT ;
    USE SIGNAL ;
    ANTENNAGATEAREA 0.213000 ;
    PORT
      LAYER met3 ;
        RECT -1.500 414.840 0.800 415.440 ;
    END
  END NN4END[3]
  PIN NN4END[4]
    DIRECTION INPUT ;
    USE SIGNAL ;
    ANTENNAGATEAREA 0.213000 ;
    PORT
      LAYER met3 ;
        RECT 499.200 227.840 501.500 228.440 ;
    END
  END NN4END[4]
  PIN NN4END[5]
    DIRECTION INPUT ;
    USE SIGNAL ;
    ANTENNAGATEAREA 0.196500 ;
    PORT
      LAYER met3 ;
        RECT 499.200 163.240 501.500 163.840 ;
    END
  END NN4END[5]
  PIN NN4END[6]
    DIRECTION INPUT ;
    USE SIGNAL ;
    ANTENNAGATEAREA 0.196500 ;
    PORT
      LAYER met3 ;
        RECT 499.200 367.240 501.500 367.840 ;
    END
  END NN4END[6]
  PIN NN4END[7]
    DIRECTION INPUT ;
    USE SIGNAL ;
    ANTENNAGATEAREA 0.196500 ;
    PORT
      LAYER met3 ;
        RECT -1.500 479.440 0.800 480.040 ;
    END
  END NN4END[7]
  PIN NN4END[8]
    DIRECTION INPUT ;
    USE SIGNAL ;
    ANTENNAGATEAREA 0.196500 ;
    PORT
      LAYER met3 ;
        RECT 499.200 380.840 501.500 381.440 ;
    END
  END NN4END[8]
  PIN NN4END[9]
    DIRECTION INPUT ;
    USE SIGNAL ;
    ANTENNAGATEAREA 0.196500 ;
    PORT
      LAYER met3 ;
        RECT 499.200 285.640 501.500 286.240 ;
    END
  END NN4END[9]
  PIN S1BEG[0]
    DIRECTION OUTPUT ;
    USE SIGNAL ;
    ANTENNADIFFAREA 1.782000 ;
    PORT
      LAYER met3 ;
        RECT 499.200 251.640 501.500 252.240 ;
    END
  END S1BEG[0]
  PIN S1BEG[1]
    DIRECTION OUTPUT ;
    USE SIGNAL ;
    ANTENNADIFFAREA 1.782000 ;
    PORT
      LAYER met2 ;
        RECT 206.170 -1.500 206.450 0.800 ;
    END
  END S1BEG[1]
  PIN S1BEG[2]
    DIRECTION OUTPUT ;
    USE SIGNAL ;
    ANTENNADIFFAREA 1.782000 ;
    PORT
      LAYER met2 ;
        RECT 141.770 499.200 142.050 501.500 ;
    END
  END S1BEG[2]
  PIN S1BEG[3]
    DIRECTION OUTPUT ;
    USE SIGNAL ;
    ANTENNADIFFAREA 1.336500 ;
    PORT
      LAYER met3 ;
        RECT -1.500 336.640 0.800 337.240 ;
    END
  END S1BEG[3]
  PIN S1END[0]
    DIRECTION INPUT ;
    USE SIGNAL ;
    ANTENNAGATEAREA 0.213000 ;
    PORT
      LAYER met3 ;
        RECT -1.500 105.440 0.800 106.040 ;
    END
  END S1END[0]
  PIN S1END[1]
    DIRECTION INPUT ;
    USE SIGNAL ;
    ANTENNAGATEAREA 0.213000 ;
    PORT
      LAYER met2 ;
        RECT 344.630 -1.500 344.910 0.800 ;
    END
  END S1END[1]
  PIN S1END[2]
    DIRECTION INPUT ;
    USE SIGNAL ;
    ANTENNAGATEAREA 0.247500 ;
    PORT
      LAYER met2 ;
        RECT 103.130 -1.500 103.410 0.800 ;
    END
  END S1END[2]
  PIN S1END[3]
    DIRECTION INPUT ;
    USE SIGNAL ;
    ANTENNAGATEAREA 0.213000 ;
    PORT
      LAYER met2 ;
        RECT 347.850 -1.500 348.130 0.800 ;
    END
  END S1END[3]
  PIN S2BEG[0]
    DIRECTION OUTPUT ;
    USE SIGNAL ;
    ANTENNADIFFAREA 1.336500 ;
    PORT
      LAYER met2 ;
        RECT 212.610 -1.500 212.890 0.800 ;
    END
  END S2BEG[0]
  PIN S2BEG[1]
    DIRECTION OUTPUT ;
    USE SIGNAL ;
    ANTENNADIFFAREA 1.336500 ;
    PORT
      LAYER met2 ;
        RECT 186.850 499.200 187.130 501.500 ;
    END
  END S2BEG[1]
  PIN S2BEG[2]
    DIRECTION OUTPUT ;
    USE SIGNAL ;
    ANTENNADIFFAREA 0.891000 ;
    PORT
      LAYER met2 ;
        RECT 209.390 499.200 209.670 501.500 ;
    END
  END S2BEG[2]
  PIN S2BEG[3]
    DIRECTION OUTPUT ;
    USE SIGNAL ;
    ANTENNADIFFAREA 1.336500 ;
    PORT
      LAYER met2 ;
        RECT 251.250 -1.500 251.530 0.800 ;
    END
  END S2BEG[3]
  PIN S2BEG[4]
    DIRECTION OUTPUT ;
    USE SIGNAL ;
    ANTENNADIFFAREA 1.782000 ;
    PORT
      LAYER met2 ;
        RECT 305.990 -1.500 306.270 0.800 ;
    END
  END S2BEG[4]
  PIN S2BEG[5]
    DIRECTION OUTPUT ;
    USE SIGNAL ;
    ANTENNADIFFAREA 1.782000 ;
    PORT
      LAYER met2 ;
        RECT 154.650 -1.500 154.930 0.800 ;
    END
  END S2BEG[5]
  PIN S2BEG[6]
    DIRECTION OUTPUT ;
    USE SIGNAL ;
    ANTENNADIFFAREA 1.782000 ;
    PORT
      LAYER met2 ;
        RECT 293.110 -1.500 293.390 0.800 ;
    END
  END S2BEG[6]
  PIN S2BEG[7]
    DIRECTION OUTPUT ;
    USE SIGNAL ;
    ANTENNADIFFAREA 1.782000 ;
    PORT
      LAYER met3 ;
        RECT -1.500 136.040 0.800 136.640 ;
    END
  END S2BEG[7]
  PIN S2BEGb[0]
    DIRECTION OUTPUT ;
    USE SIGNAL ;
    ANTENNADIFFAREA 0.445500 ;
    PORT
      LAYER met2 ;
        RECT 273.790 499.200 274.070 501.500 ;
    END
  END S2BEGb[0]
  PIN S2BEGb[1]
    DIRECTION OUTPUT ;
    USE SIGNAL ;
    ANTENNADIFFAREA 0.445500 ;
    PORT
      LAYER met2 ;
        RECT 309.210 499.200 309.490 501.500 ;
    END
  END S2BEGb[1]
  PIN S2BEGb[2]
    DIRECTION OUTPUT ;
    USE SIGNAL ;
    ANTENNADIFFAREA 0.445500 ;
    PORT
      LAYER met3 ;
        RECT 499.200 238.040 501.500 238.640 ;
    END
  END S2BEGb[2]
  PIN S2BEGb[3]
    DIRECTION OUTPUT ;
    USE SIGNAL ;
    ANTENNADIFFAREA 0.445500 ;
    PORT
      LAYER met3 ;
        RECT 499.200 241.440 501.500 242.040 ;
    END
  END S2BEGb[3]
  PIN S2BEGb[4]
    DIRECTION OUTPUT ;
    USE SIGNAL ;
    ANTENNADIFFAREA 0.445500 ;
    PORT
      LAYER met2 ;
        RECT 260.910 -1.500 261.190 0.800 ;
    END
  END S2BEGb[4]
  PIN S2BEGb[5]
    DIRECTION OUTPUT ;
    USE SIGNAL ;
    ANTENNADIFFAREA 0.445500 ;
    PORT
      LAYER met3 ;
        RECT 499.200 221.040 501.500 221.640 ;
    END
  END S2BEGb[5]
  PIN S2BEGb[6]
    DIRECTION OUTPUT ;
    USE SIGNAL ;
    ANTENNADIFFAREA 0.445500 ;
    PORT
      LAYER met2 ;
        RECT 231.930 499.200 232.210 501.500 ;
    END
  END S2BEGb[6]
  PIN S2BEGb[7]
    DIRECTION OUTPUT ;
    USE SIGNAL ;
    ANTENNADIFFAREA 0.445500 ;
    PORT
      LAYER met2 ;
        RECT 112.790 499.200 113.070 501.500 ;
    END
  END S2BEGb[7]
  PIN S2END[0]
    DIRECTION INPUT ;
    USE SIGNAL ;
    ANTENNAGATEAREA 0.159000 ;
    PORT
      LAYER met3 ;
        RECT -1.500 129.240 0.800 129.840 ;
    END
  END S2END[0]
  PIN S2END[1]
    DIRECTION INPUT ;
    USE SIGNAL ;
    ANTENNAGATEAREA 0.159000 ;
    PORT
      LAYER met2 ;
        RECT 196.510 -1.500 196.790 0.800 ;
    END
  END S2END[1]
  PIN S2END[2]
    DIRECTION INPUT ;
    USE SIGNAL ;
    ANTENNAGATEAREA 0.159000 ;
    PORT
      LAYER met3 ;
        RECT -1.500 299.240 0.800 299.840 ;
    END
  END S2END[2]
  PIN S2END[3]
    DIRECTION INPUT ;
    USE SIGNAL ;
    ANTENNAGATEAREA 0.213000 ;
    PORT
      LAYER met3 ;
        RECT -1.500 285.640 0.800 286.240 ;
    END
  END S2END[3]
  PIN S2END[4]
    DIRECTION INPUT ;
    USE SIGNAL ;
    ANTENNAGATEAREA 0.159000 ;
    PORT
      LAYER met3 ;
        RECT -1.500 238.040 0.800 238.640 ;
    END
  END S2END[4]
  PIN S2END[5]
    DIRECTION INPUT ;
    USE SIGNAL ;
    ANTENNAGATEAREA 0.213000 ;
    PORT
      LAYER met2 ;
        RECT 331.750 -1.500 332.030 0.800 ;
    END
  END S2END[5]
  PIN S2END[6]
    DIRECTION INPUT ;
    USE SIGNAL ;
    ANTENNAGATEAREA 0.159000 ;
    PORT
      LAYER met3 ;
        RECT -1.500 40.840 0.800 41.440 ;
    END
  END S2END[6]
  PIN S2END[7]
    DIRECTION INPUT ;
    USE SIGNAL ;
    ANTENNAGATEAREA 0.159000 ;
    PORT
      LAYER met2 ;
        RECT 341.410 -1.500 341.690 0.800 ;
    END
  END S2END[7]
  PIN S2MID[0]
    DIRECTION INPUT ;
    USE SIGNAL ;
    ANTENNAGATEAREA 0.213000 ;
    PORT
      LAYER met2 ;
        RECT 277.010 499.200 277.290 501.500 ;
    END
  END S2MID[0]
  PIN S2MID[1]
    DIRECTION INPUT ;
    USE SIGNAL ;
    ANTENNAGATEAREA 0.196500 ;
    PORT
      LAYER met2 ;
        RECT 251.250 499.200 251.530 501.500 ;
    END
  END S2MID[1]
  PIN S2MID[2]
    DIRECTION INPUT ;
    USE SIGNAL ;
    ANTENNAGATEAREA 0.213000 ;
    PORT
      LAYER met3 ;
        RECT 499.200 57.840 501.500 58.440 ;
    END
  END S2MID[2]
  PIN S2MID[3]
    DIRECTION INPUT ;
    USE SIGNAL ;
    ANTENNAGATEAREA 0.213000 ;
    PORT
      LAYER met3 ;
        RECT 499.200 282.240 501.500 282.840 ;
    END
  END S2MID[3]
  PIN S2MID[4]
    DIRECTION INPUT ;
    USE SIGNAL ;
    ANTENNAGATEAREA 0.213000 ;
    PORT
      LAYER met2 ;
        RECT 264.130 -1.500 264.410 0.800 ;
    END
  END S2MID[4]
  PIN S2MID[5]
    DIRECTION INPUT ;
    USE SIGNAL ;
    ANTENNAGATEAREA 0.213000 ;
    PORT
      LAYER met3 ;
        RECT 499.200 217.640 501.500 218.240 ;
    END
  END S2MID[5]
  PIN S2MID[6]
    DIRECTION INPUT ;
    USE SIGNAL ;
    ANTENNAGATEAREA 0.213000 ;
    PORT
      LAYER met2 ;
        RECT 222.270 499.200 222.550 501.500 ;
    END
  END S2MID[6]
  PIN S2MID[7]
    DIRECTION INPUT ;
    USE SIGNAL ;
    ANTENNAGATEAREA 0.213000 ;
    PORT
      LAYER met2 ;
        RECT 119.230 499.200 119.510 501.500 ;
    END
  END S2MID[7]
  PIN S4BEG[0]
    DIRECTION OUTPUT ;
    USE SIGNAL ;
    ANTENNADIFFAREA 0.445500 ;
    PORT
      LAYER met2 ;
        RECT 457.330 -1.500 457.610 0.800 ;
    END
  END S4BEG[0]
  PIN S4BEG[10]
    DIRECTION OUTPUT ;
    USE SIGNAL ;
    ANTENNADIFFAREA 0.445500 ;
    PORT
      LAYER met2 ;
        RECT 186.850 -1.500 187.130 0.800 ;
    END
  END S4BEG[10]
  PIN S4BEG[11]
    DIRECTION OUTPUT ;
    USE SIGNAL ;
    ANTENNADIFFAREA 0.445500 ;
    PORT
      LAYER met2 ;
        RECT 322.090 499.200 322.370 501.500 ;
    END
  END S4BEG[11]
  PIN S4BEG[12]
    DIRECTION OUTPUT ;
    USE SIGNAL ;
    ANTENNADIFFAREA 0.445500 ;
    PORT
      LAYER met3 ;
        RECT -1.500 231.240 0.800 231.840 ;
    END
  END S4BEG[12]
  PIN S4BEG[13]
    DIRECTION OUTPUT ;
    USE SIGNAL ;
    ANTENNADIFFAREA 1.336500 ;
    PORT
      LAYER met3 ;
        RECT -1.500 278.840 0.800 279.440 ;
    END
  END S4BEG[13]
  PIN S4BEG[14]
    DIRECTION OUTPUT ;
    USE SIGNAL ;
    ANTENNADIFFAREA 1.336500 ;
    PORT
      LAYER met3 ;
        RECT -1.500 217.640 0.800 218.240 ;
    END
  END S4BEG[14]
  PIN S4BEG[15]
    DIRECTION OUTPUT ;
    USE SIGNAL ;
    ANTENNADIFFAREA 0.445500 ;
    PORT
      LAYER met3 ;
        RECT -1.500 207.440 0.800 208.040 ;
    END
  END S4BEG[15]
  PIN S4BEG[1]
    DIRECTION OUTPUT ;
    USE SIGNAL ;
    ANTENNADIFFAREA 0.445500 ;
    PORT
      LAYER met3 ;
        RECT 499.200 23.840 501.500 24.440 ;
    END
  END S4BEG[1]
  PIN S4BEG[2]
    DIRECTION OUTPUT ;
    USE SIGNAL ;
    ANTENNADIFFAREA 0.445500 ;
    PORT
      LAYER met3 ;
        RECT -1.500 418.240 0.800 418.840 ;
    END
  END S4BEG[2]
  PIN S4BEG[3]
    DIRECTION OUTPUT ;
    USE SIGNAL ;
    ANTENNADIFFAREA 0.445500 ;
    PORT
      LAYER met2 ;
        RECT 161.090 499.200 161.370 501.500 ;
    END
  END S4BEG[3]
  PIN S4BEG[4]
    DIRECTION OUTPUT ;
    USE SIGNAL ;
    ANTENNADIFFAREA 0.445500 ;
    PORT
      LAYER met2 ;
        RECT 486.310 -1.500 486.590 0.800 ;
    END
  END S4BEG[4]
  PIN S4BEG[5]
    DIRECTION OUTPUT ;
    USE SIGNAL ;
    ANTENNADIFFAREA 0.445500 ;
    PORT
      LAYER met3 ;
        RECT 499.200 493.040 501.500 493.640 ;
    END
  END S4BEG[5]
  PIN S4BEG[6]
    DIRECTION OUTPUT ;
    USE SIGNAL ;
    ANTENNADIFFAREA 0.445500 ;
    PORT
      LAYER met3 ;
        RECT -1.500 57.840 0.800 58.440 ;
    END
  END S4BEG[6]
  PIN S4BEG[7]
    DIRECTION OUTPUT ;
    USE SIGNAL ;
    ANTENNADIFFAREA 0.445500 ;
    PORT
      LAYER met2 ;
        RECT 454.110 -1.500 454.390 0.800 ;
    END
  END S4BEG[7]
  PIN S4BEG[8]
    DIRECTION OUTPUT ;
    USE SIGNAL ;
    ANTENNADIFFAREA 0.445500 ;
    PORT
      LAYER met2 ;
        RECT 354.290 -1.500 354.570 0.800 ;
    END
  END S4BEG[8]
  PIN S4BEG[9]
    DIRECTION OUTPUT ;
    USE SIGNAL ;
    ANTENNADIFFAREA 0.445500 ;
    PORT
      LAYER met3 ;
        RECT 499.200 404.640 501.500 405.240 ;
    END
  END S4BEG[9]
  PIN S4END[0]
    DIRECTION INPUT ;
    USE SIGNAL ;
    ANTENNAGATEAREA 0.213000 ;
    PORT
      LAYER met3 ;
        RECT -1.500 343.440 0.800 344.040 ;
    END
  END S4END[0]
  PIN S4END[10]
    DIRECTION INPUT ;
    USE SIGNAL ;
    ANTENNAGATEAREA 0.196500 ;
    PORT
      LAYER met3 ;
        RECT -1.500 61.240 0.800 61.840 ;
    END
  END S4END[10]
  PIN S4END[11]
    DIRECTION INPUT ;
    USE SIGNAL ;
    ANTENNAGATEAREA 0.196500 ;
    PORT
      LAYER met2 ;
        RECT 412.250 -1.500 412.530 0.800 ;
    END
  END S4END[11]
  PIN S4END[12]
    DIRECTION INPUT ;
    USE SIGNAL ;
    ANTENNAGATEAREA 0.196500 ;
    PORT
      LAYER met2 ;
        RECT 338.190 -1.500 338.470 0.800 ;
    END
  END S4END[12]
  PIN S4END[13]
    DIRECTION INPUT ;
    USE SIGNAL ;
    ANTENNAGATEAREA 0.196500 ;
    PORT
      LAYER met3 ;
        RECT 499.200 408.040 501.500 408.640 ;
    END
  END S4END[13]
  PIN S4END[14]
    DIRECTION INPUT ;
    USE SIGNAL ;
    ANTENNAGATEAREA 0.196500 ;
    PORT
      LAYER met2 ;
        RECT 202.950 -1.500 203.230 0.800 ;
    END
  END S4END[14]
  PIN S4END[15]
    DIRECTION INPUT ;
    USE SIGNAL ;
    ANTENNAGATEAREA 0.196500 ;
    PORT
      LAYER met2 ;
        RECT 318.870 499.200 319.150 501.500 ;
    END
  END S4END[15]
  PIN S4END[1]
    DIRECTION INPUT ;
    USE SIGNAL ;
    ANTENNAGATEAREA 0.159000 ;
    PORT
      LAYER met2 ;
        RECT 199.730 -1.500 200.010 0.800 ;
    END
  END S4END[1]
  PIN S4END[2]
    DIRECTION INPUT ;
    USE SIGNAL ;
    ANTENNAGATEAREA 0.159000 ;
    PORT
      LAYER met3 ;
        RECT -1.500 295.840 0.800 296.440 ;
    END
  END S4END[2]
  PIN S4END[3]
    DIRECTION INPUT ;
    USE SIGNAL ;
    ANTENNAGATEAREA 0.213000 ;
    PORT
      LAYER met3 ;
        RECT -1.500 323.040 0.800 323.640 ;
    END
  END S4END[3]
  PIN S4END[4]
    DIRECTION INPUT ;
    USE SIGNAL ;
    ANTENNAGATEAREA 0.196500 ;
    PORT
      LAYER met2 ;
        RECT 409.030 -1.500 409.310 0.800 ;
    END
  END S4END[4]
  PIN S4END[5]
    DIRECTION INPUT ;
    USE SIGNAL ;
    ANTENNAGATEAREA 0.196500 ;
    PORT
      LAYER met3 ;
        RECT 499.200 20.440 501.500 21.040 ;
    END
  END S4END[5]
  PIN S4END[6]
    DIRECTION INPUT ;
    USE SIGNAL ;
    ANTENNAGATEAREA 0.196500 ;
    PORT
      LAYER met3 ;
        RECT -1.500 428.440 0.800 429.040 ;
    END
  END S4END[6]
  PIN S4END[7]
    DIRECTION INPUT ;
    USE SIGNAL ;
    ANTENNAGATEAREA 0.196500 ;
    PORT
      LAYER met2 ;
        RECT 157.870 499.200 158.150 501.500 ;
    END
  END S4END[7]
  PIN S4END[8]
    DIRECTION INPUT ;
    USE SIGNAL ;
    ANTENNAGATEAREA 0.196500 ;
    PORT
      LAYER met2 ;
        RECT 483.090 -1.500 483.370 0.800 ;
    END
  END S4END[8]
  PIN S4END[9]
    DIRECTION INPUT ;
    USE SIGNAL ;
    ANTENNAGATEAREA 0.196500 ;
    PORT
      LAYER met3 ;
        RECT 499.200 394.440 501.500 395.040 ;
    END
  END S4END[9]
  PIN SS4BEG[0]
    DIRECTION OUTPUT ;
    USE SIGNAL ;
    ANTENNADIFFAREA 0.445500 ;
    PORT
      LAYER met3 ;
        RECT 499.200 309.440 501.500 310.040 ;
    END
  END SS4BEG[0]
  PIN SS4BEG[10]
    DIRECTION OUTPUT ;
    USE SIGNAL ;
    ANTENNADIFFAREA 0.445500 ;
    PORT
      LAYER met3 ;
        RECT 499.200 489.640 501.500 490.240 ;
    END
  END SS4BEG[10]
  PIN SS4BEG[11]
    DIRECTION OUTPUT ;
    USE SIGNAL ;
    ANTENNADIFFAREA 0.445500 ;
    PORT
      LAYER met3 ;
        RECT 499.200 326.440 501.500 327.040 ;
    END
  END SS4BEG[11]
  PIN SS4BEG[12]
    DIRECTION OUTPUT ;
    USE SIGNAL ;
    ANTENNADIFFAREA 1.336500 ;
    PORT
      LAYER met2 ;
        RECT 228.710 -1.500 228.990 0.800 ;
    END
  END SS4BEG[12]
  PIN SS4BEG[13]
    DIRECTION OUTPUT ;
    USE SIGNAL ;
    ANTENNADIFFAREA 1.782000 ;
    PORT
      LAYER met3 ;
        RECT 499.200 146.240 501.500 146.840 ;
    END
  END SS4BEG[13]
  PIN SS4BEG[14]
    DIRECTION OUTPUT ;
    USE SIGNAL ;
    ANTENNADIFFAREA 0.891000 ;
    PORT
      LAYER met3 ;
        RECT -1.500 180.240 0.800 180.840 ;
    END
  END SS4BEG[14]
  PIN SS4BEG[15]
    DIRECTION OUTPUT ;
    USE SIGNAL ;
    ANTENNADIFFAREA 1.782000 ;
    PORT
      LAYER met2 ;
        RECT 299.550 -1.500 299.830 0.800 ;
    END
  END SS4BEG[15]
  PIN SS4BEG[1]
    DIRECTION OUTPUT ;
    USE SIGNAL ;
    ANTENNADIFFAREA 0.445500 ;
    PORT
      LAYER met2 ;
        RECT 466.990 -1.500 467.270 0.800 ;
    END
  END SS4BEG[1]
  PIN SS4BEG[2]
    DIRECTION OUTPUT ;
    USE SIGNAL ;
    ANTENNADIFFAREA 0.445500 ;
    PORT
      LAYER met2 ;
        RECT 248.030 -1.500 248.310 0.800 ;
    END
  END SS4BEG[2]
  PIN SS4BEG[3]
    DIRECTION OUTPUT ;
    USE SIGNAL ;
    ANTENNADIFFAREA 0.445500 ;
    PORT
      LAYER met3 ;
        RECT 499.200 323.040 501.500 323.640 ;
    END
  END SS4BEG[3]
  PIN SS4BEG[4]
    DIRECTION OUTPUT ;
    USE SIGNAL ;
    ANTENNADIFFAREA 0.445500 ;
    PORT
      LAYER met3 ;
        RECT -1.500 486.240 0.800 486.840 ;
    END
  END SS4BEG[4]
  PIN SS4BEG[5]
    DIRECTION OUTPUT ;
    USE SIGNAL ;
    ANTENNADIFFAREA 0.445500 ;
    PORT
      LAYER met2 ;
        RECT 22.630 -1.500 22.910 0.800 ;
    END
  END SS4BEG[5]
  PIN SS4BEG[6]
    DIRECTION OUTPUT ;
    USE SIGNAL ;
    ANTENNADIFFAREA 0.445500 ;
    PORT
      LAYER met2 ;
        RECT 199.730 499.200 200.010 501.500 ;
    END
  END SS4BEG[6]
  PIN SS4BEG[7]
    DIRECTION OUTPUT ;
    USE SIGNAL ;
    ANTENNADIFFAREA 0.445500 ;
    PORT
      LAYER met3 ;
        RECT 499.200 411.440 501.500 412.040 ;
    END
  END SS4BEG[7]
  PIN SS4BEG[8]
    DIRECTION OUTPUT ;
    USE SIGNAL ;
    ANTENNADIFFAREA 0.445500 ;
    PORT
      LAYER met3 ;
        RECT 499.200 112.240 501.500 112.840 ;
    END
  END SS4BEG[8]
  PIN SS4BEG[9]
    DIRECTION OUTPUT ;
    USE SIGNAL ;
    ANTENNADIFFAREA 0.445500 ;
    PORT
      LAYER met2 ;
        RECT 244.810 499.200 245.090 501.500 ;
    END
  END SS4BEG[9]
  PIN SS4END[0]
    DIRECTION INPUT ;
    USE SIGNAL ;
    ANTENNAGATEAREA 0.159000 ;
    PORT
      LAYER met3 ;
        RECT -1.500 316.240 0.800 316.840 ;
    END
  END SS4END[0]
  PIN SS4END[10]
    DIRECTION INPUT ;
    USE SIGNAL ;
    ANTENNAGATEAREA 0.196500 ;
    PORT
      LAYER met2 ;
        RECT 196.510 499.200 196.790 501.500 ;
    END
  END SS4END[10]
  PIN SS4END[11]
    DIRECTION INPUT ;
    USE SIGNAL ;
    ANTENNAGATEAREA 0.196500 ;
    PORT
      LAYER met3 ;
        RECT 499.200 428.440 501.500 429.040 ;
    END
  END SS4END[11]
  PIN SS4END[12]
    DIRECTION INPUT ;
    USE SIGNAL ;
    ANTENNAGATEAREA 0.196500 ;
    PORT
      LAYER met3 ;
        RECT 499.200 115.640 501.500 116.240 ;
    END
  END SS4END[12]
  PIN SS4END[13]
    DIRECTION INPUT ;
    USE SIGNAL ;
    ANTENNAGATEAREA 0.196500 ;
    PORT
      LAYER met2 ;
        RECT 238.370 499.200 238.650 501.500 ;
    END
  END SS4END[13]
  PIN SS4END[14]
    DIRECTION INPUT ;
    USE SIGNAL ;
    ANTENNAGATEAREA 0.196500 ;
    PORT
      LAYER met3 ;
        RECT 499.200 431.840 501.500 432.440 ;
    END
  END SS4END[14]
  PIN SS4END[15]
    DIRECTION INPUT ;
    USE SIGNAL ;
    ANTENNAGATEAREA 0.196500 ;
    PORT
      LAYER met3 ;
        RECT 499.200 391.040 501.500 391.640 ;
    END
  END SS4END[15]
  PIN SS4END[1]
    DIRECTION INPUT ;
    USE SIGNAL ;
    ANTENNAGATEAREA 0.159000 ;
    PORT
      LAYER met2 ;
        RECT 183.630 -1.500 183.910 0.800 ;
    END
  END SS4END[1]
  PIN SS4END[2]
    DIRECTION INPUT ;
    USE SIGNAL ;
    ANTENNAGATEAREA 0.213000 ;
    PORT
      LAYER met3 ;
        RECT -1.500 234.640 0.800 235.240 ;
    END
  END SS4END[2]
  PIN SS4END[3]
    DIRECTION INPUT ;
    USE SIGNAL ;
    ANTENNAGATEAREA 0.159000 ;
    PORT
      LAYER met3 ;
        RECT -1.500 170.040 0.800 170.640 ;
    END
  END SS4END[3]
  PIN SS4END[4]
    DIRECTION INPUT ;
    USE SIGNAL ;
    ANTENNAGATEAREA 0.196500 ;
    PORT
      LAYER met3 ;
        RECT 499.200 306.040 501.500 306.640 ;
    END
  END SS4END[4]
  PIN SS4END[5]
    DIRECTION INPUT ;
    USE SIGNAL ;
    ANTENNAGATEAREA 0.196500 ;
    PORT
      LAYER met2 ;
        RECT 460.550 -1.500 460.830 0.800 ;
    END
  END SS4END[5]
  PIN SS4END[6]
    DIRECTION INPUT ;
    USE SIGNAL ;
    ANTENNAGATEAREA 0.196500 ;
    PORT
      LAYER met2 ;
        RECT 254.470 -1.500 254.750 0.800 ;
    END
  END SS4END[6]
  PIN SS4END[7]
    DIRECTION INPUT ;
    USE SIGNAL ;
    ANTENNAGATEAREA 0.196500 ;
    PORT
      LAYER met3 ;
        RECT 499.200 452.240 501.500 452.840 ;
    END
  END SS4END[7]
  PIN SS4END[8]
    DIRECTION INPUT ;
    USE SIGNAL ;
    ANTENNAGATEAREA 0.196500 ;
    PORT
      LAYER met3 ;
        RECT -1.500 476.040 0.800 476.640 ;
    END
  END SS4END[8]
  PIN SS4END[9]
    DIRECTION INPUT ;
    USE SIGNAL ;
    ANTENNAGATEAREA 0.196500 ;
    PORT
      LAYER met2 ;
        RECT 16.190 -1.500 16.470 0.800 ;
    END
  END SS4END[9]
  PIN UserCLK
    DIRECTION INPUT ;
    USE SIGNAL ;
    ANTENNAGATEAREA 0.247500 ;
    PORT
      LAYER met2 ;
        RECT 402.590 499.200 402.870 501.500 ;
    END
  END UserCLK
  PIN UserCLKo
    DIRECTION OUTPUT ;
    USE SIGNAL ;
    ANTENNADIFFAREA 0.445500 ;
    PORT
      LAYER met2 ;
        RECT 380.050 499.200 380.330 501.500 ;
    END
  END UserCLKo
  PIN VGND
    DIRECTION INOUT ;
    USE GROUND ;
    PORT
      LAYER met4 ;
        RECT 23.880 5.200 25.480 492.560 ;
    END
    PORT
      LAYER met4 ;
        RECT 177.480 5.200 179.080 492.560 ;
    END
    PORT
      LAYER met4 ;
        RECT 331.080 5.200 332.680 492.560 ;
    END
    PORT
      LAYER met4 ;
        RECT 484.680 5.200 486.280 492.560 ;
    END
    PORT
      LAYER met5 ;
        RECT 4.820 24.590 495.200 26.190 ;
    END
    PORT
      LAYER met5 ;
        RECT 4.820 177.770 495.200 179.370 ;
    END
    PORT
      LAYER met5 ;
        RECT 4.820 330.950 495.200 332.550 ;
    END
    PORT
      LAYER met5 ;
        RECT 4.820 484.130 495.200 485.730 ;
    END
  END VGND
  PIN VPWR
    DIRECTION INOUT ;
    USE POWER ;
    PORT
      LAYER met4 ;
        RECT 20.580 5.200 22.180 492.560 ;
    END
    PORT
      LAYER met4 ;
        RECT 174.180 5.200 175.780 492.560 ;
    END
    PORT
      LAYER met4 ;
        RECT 327.780 5.200 329.380 492.560 ;
    END
    PORT
      LAYER met4 ;
        RECT 481.380 5.200 482.980 492.560 ;
    END
    PORT
      LAYER met5 ;
        RECT 4.820 21.290 495.200 22.890 ;
    END
    PORT
      LAYER met5 ;
        RECT 4.820 174.470 495.200 176.070 ;
    END
    PORT
      LAYER met5 ;
        RECT 4.820 327.650 495.200 329.250 ;
    END
    PORT
      LAYER met5 ;
        RECT 4.820 480.830 495.200 482.430 ;
    END
  END VPWR
  PIN W1BEG[0]
    DIRECTION OUTPUT ;
    USE SIGNAL ;
    ANTENNADIFFAREA 1.336500 ;
    PORT
      LAYER met2 ;
        RECT 267.350 -1.500 267.630 0.800 ;
    END
  END W1BEG[0]
  PIN W1BEG[1]
    DIRECTION OUTPUT ;
    USE SIGNAL ;
    ANTENNADIFFAREA 0.795200 ;
    PORT
      LAYER met2 ;
        RECT 222.270 -1.500 222.550 0.800 ;
    END
  END W1BEG[1]
  PIN W1BEG[2]
    DIRECTION OUTPUT ;
    USE SIGNAL ;
    ANTENNADIFFAREA 1.782000 ;
    PORT
      LAYER met3 ;
        RECT -1.500 353.640 0.800 354.240 ;
    END
  END W1BEG[2]
  PIN W1BEG[3]
    DIRECTION OUTPUT ;
    USE SIGNAL ;
    ANTENNADIFFAREA 1.782000 ;
    PORT
      LAYER met2 ;
        RECT 177.190 499.200 177.470 501.500 ;
    END
  END W1BEG[3]
  PIN W1END[0]
    DIRECTION INPUT ;
    USE SIGNAL ;
    ANTENNAGATEAREA 0.213000 ;
    PORT
      LAYER met3 ;
        RECT -1.500 102.040 0.800 102.640 ;
    END
  END W1END[0]
  PIN W1END[1]
    DIRECTION INPUT ;
    USE SIGNAL ;
    ANTENNAGATEAREA 0.213000 ;
    PORT
      LAYER met2 ;
        RECT 325.310 -1.500 325.590 0.800 ;
    END
  END W1END[1]
  PIN W1END[2]
    DIRECTION INPUT ;
    USE SIGNAL ;
    ANTENNAGATEAREA 0.213000 ;
    PORT
      LAYER met2 ;
        RECT 106.350 -1.500 106.630 0.800 ;
    END
  END W1END[2]
  PIN W1END[3]
    DIRECTION INPUT ;
    USE SIGNAL ;
    ANTENNAGATEAREA 0.126000 ;
    PORT
      LAYER met2 ;
        RECT 370.390 -1.500 370.670 0.800 ;
    END
  END W1END[3]
  PIN W2BEG[0]
    DIRECTION OUTPUT ;
    USE SIGNAL ;
    ANTENNADIFFAREA 1.336500 ;
    PORT
      LAYER met2 ;
        RECT 231.930 -1.500 232.210 0.800 ;
    END
  END W2BEG[0]
  PIN W2BEG[1]
    DIRECTION OUTPUT ;
    USE SIGNAL ;
    ANTENNADIFFAREA 1.336500 ;
    PORT
      LAYER met3 ;
        RECT -1.500 411.440 0.800 412.040 ;
    END
  END W2BEG[1]
  PIN W2BEG[2]
    DIRECTION OUTPUT ;
    USE SIGNAL ;
    ANTENNADIFFAREA 1.782000 ;
    PORT
      LAYER met3 ;
        RECT -1.500 333.240 0.800 333.840 ;
    END
  END W2BEG[2]
  PIN W2BEG[3]
    DIRECTION OUTPUT ;
    USE SIGNAL ;
    ANTENNADIFFAREA 1.336500 ;
    PORT
      LAYER met3 ;
        RECT -1.500 244.840 0.800 245.440 ;
    END
  END W2BEG[3]
  PIN W2BEG[4]
    DIRECTION OUTPUT ;
    USE SIGNAL ;
    ANTENNADIFFAREA 1.336500 ;
    PORT
      LAYER met2 ;
        RECT 360.730 -1.500 361.010 0.800 ;
    END
  END W2BEG[4]
  PIN W2BEG[5]
    DIRECTION OUTPUT ;
    USE SIGNAL ;
    ANTENNADIFFAREA 1.336500 ;
    PORT
      LAYER met2 ;
        RECT 128.890 -1.500 129.170 0.800 ;
    END
  END W2BEG[5]
  PIN W2BEG[6]
    DIRECTION OUTPUT ;
    USE SIGNAL ;
    ANTENNADIFFAREA 1.782000 ;
    PORT
      LAYER met3 ;
        RECT 499.200 295.840 501.500 296.440 ;
    END
  END W2BEG[6]
  PIN W2BEG[7]
    DIRECTION OUTPUT ;
    USE SIGNAL ;
    ANTENNADIFFAREA 1.336500 ;
    PORT
      LAYER met3 ;
        RECT -1.500 149.640 0.800 150.240 ;
    END
  END W2BEG[7]
  PIN W2BEGb[0]
    DIRECTION OUTPUT ;
    USE SIGNAL ;
    ANTENNADIFFAREA 0.445500 ;
    PORT
      LAYER met2 ;
        RECT 260.910 499.200 261.190 501.500 ;
    END
  END W2BEGb[0]
  PIN W2BEGb[1]
    DIRECTION OUTPUT ;
    USE SIGNAL ;
    ANTENNADIFFAREA 0.445500 ;
    PORT
      LAYER met2 ;
        RECT 302.770 499.200 303.050 501.500 ;
    END
  END W2BEGb[1]
  PIN W2BEGb[2]
    DIRECTION OUTPUT ;
    USE SIGNAL ;
    ANTENNADIFFAREA 0.445500 ;
    PORT
      LAYER met3 ;
        RECT 499.200 248.240 501.500 248.840 ;
    END
  END W2BEGb[2]
  PIN W2BEGb[3]
    DIRECTION OUTPUT ;
    USE SIGNAL ;
    ANTENNADIFFAREA 0.445500 ;
    PORT
      LAYER met3 ;
        RECT 499.200 255.040 501.500 255.640 ;
    END
  END W2BEGb[3]
  PIN W2BEGb[4]
    DIRECTION OUTPUT ;
    USE SIGNAL ;
    ANTENNADIFFAREA 0.445500 ;
    PORT
      LAYER met2 ;
        RECT 270.570 -1.500 270.850 0.800 ;
    END
  END W2BEGb[4]
  PIN W2BEGb[5]
    DIRECTION OUTPUT ;
    USE SIGNAL ;
    ANTENNADIFFAREA 0.445500 ;
    PORT
      LAYER met3 ;
        RECT 499.200 224.440 501.500 225.040 ;
    END
  END W2BEGb[5]
  PIN W2BEGb[6]
    DIRECTION OUTPUT ;
    USE SIGNAL ;
    ANTENNADIFFAREA 0.445500 ;
    PORT
      LAYER met2 ;
        RECT 212.610 499.200 212.890 501.500 ;
    END
  END W2BEGb[6]
  PIN W2BEGb[7]
    DIRECTION OUTPUT ;
    USE SIGNAL ;
    ANTENNADIFFAREA 0.445500 ;
    PORT
      LAYER met2 ;
        RECT 96.690 499.200 96.970 501.500 ;
    END
  END W2BEGb[7]
  PIN W2END[0]
    DIRECTION INPUT ;
    USE SIGNAL ;
    ANTENNAGATEAREA 0.213000 ;
    PORT
      LAYER met3 ;
        RECT -1.500 221.040 0.800 221.640 ;
    END
  END W2END[0]
  PIN W2END[1]
    DIRECTION INPUT ;
    USE SIGNAL ;
    ANTENNAGATEAREA 0.159000 ;
    PORT
      LAYER met2 ;
        RECT 190.070 -1.500 190.350 0.800 ;
    END
  END W2END[1]
  PIN W2END[2]
    DIRECTION INPUT ;
    USE SIGNAL ;
    ANTENNAGATEAREA 0.159000 ;
    PORT
      LAYER met3 ;
        RECT -1.500 275.440 0.800 276.040 ;
    END
  END W2END[2]
  PIN W2END[3]
    DIRECTION INPUT ;
    USE SIGNAL ;
    ANTENNAGATEAREA 0.159000 ;
    PORT
      LAYER met3 ;
        RECT -1.500 289.040 0.800 289.640 ;
    END
  END W2END[3]
  PIN W2END[4]
    DIRECTION INPUT ;
    USE SIGNAL ;
    ANTENNAGATEAREA 0.159000 ;
    PORT
      LAYER met3 ;
        RECT -1.500 193.840 0.800 194.440 ;
    END
  END W2END[4]
  PIN W2END[5]
    DIRECTION INPUT ;
    USE SIGNAL ;
    ANTENNAGATEAREA 0.196500 ;
    PORT
      LAYER met2 ;
        RECT 273.790 -1.500 274.070 0.800 ;
    END
  END W2END[5]
  PIN W2END[6]
    DIRECTION INPUT ;
    USE SIGNAL ;
    ANTENNAGATEAREA 0.126000 ;
    PORT
      LAYER met3 ;
        RECT -1.500 183.640 0.800 184.240 ;
    END
  END W2END[6]
  PIN W2END[7]
    DIRECTION INPUT ;
    USE SIGNAL ;
    ANTENNAGATEAREA 0.159000 ;
    PORT
      LAYER met2 ;
        RECT 161.090 -1.500 161.370 0.800 ;
    END
  END W2END[7]
  PIN W2MID[0]
    DIRECTION INPUT ;
    USE SIGNAL ;
    ANTENNAGATEAREA 0.213000 ;
    PORT
      LAYER met2 ;
        RECT 283.450 499.200 283.730 501.500 ;
    END
  END W2MID[0]
  PIN W2MID[1]
    DIRECTION INPUT ;
    USE SIGNAL ;
    ANTENNAGATEAREA 0.126000 ;
    PORT
      LAYER met2 ;
        RECT 305.990 499.200 306.270 501.500 ;
    END
  END W2MID[1]
  PIN W2MID[2]
    DIRECTION INPUT ;
    USE SIGNAL ;
    ANTENNAGATEAREA 0.213000 ;
    PORT
      LAYER met3 ;
        RECT 499.200 51.040 501.500 51.640 ;
    END
  END W2MID[2]
  PIN W2MID[3]
    DIRECTION INPUT ;
    USE SIGNAL ;
    ANTENNAGATEAREA 0.213000 ;
    PORT
      LAYER met3 ;
        RECT 499.200 258.440 501.500 259.040 ;
    END
  END W2MID[3]
  PIN W2MID[4]
    DIRECTION INPUT ;
    USE SIGNAL ;
    ANTENNAGATEAREA 0.213000 ;
    PORT
      LAYER met2 ;
        RECT 286.670 -1.500 286.950 0.800 ;
    END
  END W2MID[4]
  PIN W2MID[5]
    DIRECTION INPUT ;
    USE SIGNAL ;
    ANTENNAGATEAREA 0.159000 ;
    PORT
      LAYER met3 ;
        RECT 499.200 125.840 501.500 126.440 ;
    END
  END W2MID[5]
  PIN W2MID[6]
    DIRECTION INPUT ;
    USE SIGNAL ;
    ANTENNAGATEAREA 0.213000 ;
    PORT
      LAYER met2 ;
        RECT 215.830 499.200 216.110 501.500 ;
    END
  END W2MID[6]
  PIN W2MID[7]
    DIRECTION INPUT ;
    USE SIGNAL ;
    ANTENNAGATEAREA 0.213000 ;
    PORT
      LAYER met2 ;
        RECT 61.270 499.200 61.550 501.500 ;
    END
  END W2MID[7]
  PIN W6BEG[0]
    DIRECTION OUTPUT ;
    USE SIGNAL ;
    ANTENNADIFFAREA 0.445500 ;
    PORT
      LAYER met3 ;
        RECT -1.500 200.640 0.800 201.240 ;
    END
  END W6BEG[0]
  PIN W6BEG[10]
    DIRECTION OUTPUT ;
    USE SIGNAL ;
    ANTENNADIFFAREA 1.782000 ;
    PORT
      LAYER met2 ;
        RECT 367.170 -1.500 367.450 0.800 ;
    END
  END W6BEG[10]
  PIN W6BEG[11]
    DIRECTION OUTPUT ;
    USE SIGNAL ;
    ANTENNADIFFAREA 1.782000 ;
    PORT
      LAYER met3 ;
        RECT 499.200 180.240 501.500 180.840 ;
    END
  END W6BEG[11]
  PIN W6BEG[1]
    DIRECTION OUTPUT ;
    USE SIGNAL ;
    ANTENNADIFFAREA 0.445500 ;
    PORT
      LAYER met3 ;
        RECT 499.200 68.040 501.500 68.640 ;
    END
  END W6BEG[1]
  PIN W6BEG[2]
    DIRECTION OUTPUT ;
    USE SIGNAL ;
    ANTENNADIFFAREA 0.445500 ;
    PORT
      LAYER met2 ;
        RECT 415.470 -1.500 415.750 0.800 ;
    END
  END W6BEG[2]
  PIN W6BEG[3]
    DIRECTION OUTPUT ;
    USE SIGNAL ;
    ANTENNADIFFAREA 0.445500 ;
    PORT
      LAYER met3 ;
        RECT 499.200 88.440 501.500 89.040 ;
    END
  END W6BEG[3]
  PIN W6BEG[4]
    DIRECTION OUTPUT ;
    USE SIGNAL ;
    ANTENNADIFFAREA 0.445500 ;
    PORT
      LAYER met3 ;
        RECT 499.200 363.840 501.500 364.440 ;
    END
  END W6BEG[4]
  PIN W6BEG[5]
    DIRECTION OUTPUT ;
    USE SIGNAL ;
    ANTENNADIFFAREA 0.445500 ;
    PORT
      LAYER met3 ;
        RECT 499.200 496.440 501.500 497.040 ;
    END
  END W6BEG[5]
  PIN W6BEG[6]
    DIRECTION OUTPUT ;
    USE SIGNAL ;
    ANTENNADIFFAREA 0.445500 ;
    PORT
      LAYER met2 ;
        RECT 428.350 -1.500 428.630 0.800 ;
    END
  END W6BEG[6]
  PIN W6BEG[7]
    DIRECTION OUTPUT ;
    USE SIGNAL ;
    ANTENNADIFFAREA 0.445500 ;
    PORT
      LAYER met3 ;
        RECT 499.200 149.640 501.500 150.240 ;
    END
  END W6BEG[7]
  PIN W6BEG[8]
    DIRECTION OUTPUT ;
    USE SIGNAL ;
    ANTENNADIFFAREA 0.445500 ;
    PORT
      LAYER met3 ;
        RECT 499.200 244.840 501.500 245.440 ;
    END
  END W6BEG[8]
  PIN W6BEG[9]
    DIRECTION OUTPUT ;
    USE SIGNAL ;
    ANTENNADIFFAREA 0.445500 ;
    PORT
      LAYER met2 ;
        RECT 116.010 499.200 116.290 501.500 ;
    END
  END W6BEG[9]
  PIN W6END[0]
    DIRECTION INPUT ;
    USE SIGNAL ;
    ANTENNAGATEAREA 0.213000 ;
    PORT
      LAYER met3 ;
        RECT -1.500 312.840 0.800 313.440 ;
    END
  END W6END[0]
  PIN W6END[10]
    DIRECTION INPUT ;
    USE SIGNAL ;
    ANTENNAGATEAREA 0.196500 ;
    PORT
      LAYER met3 ;
        RECT 499.200 289.040 501.500 289.640 ;
    END
  END W6END[10]
  PIN W6END[11]
    DIRECTION INPUT ;
    USE SIGNAL ;
    ANTENNAGATEAREA 0.196500 ;
    PORT
      LAYER met2 ;
        RECT 135.330 499.200 135.610 501.500 ;
    END
  END W6END[11]
  PIN W6END[1]
    DIRECTION INPUT ;
    USE SIGNAL ;
    ANTENNAGATEAREA 0.247500 ;
    PORT
      LAYER met3 ;
        RECT -1.500 122.440 0.800 123.040 ;
    END
  END W6END[1]
  PIN W6END[2]
    DIRECTION INPUT ;
    USE SIGNAL ;
    ANTENNAGATEAREA 0.196500 ;
    PORT
      LAYER met3 ;
        RECT -1.500 197.240 0.800 197.840 ;
    END
  END W6END[2]
  PIN W6END[3]
    DIRECTION INPUT ;
    USE SIGNAL ;
    ANTENNAGATEAREA 0.196500 ;
    PORT
      LAYER met3 ;
        RECT 499.200 71.440 501.500 72.040 ;
    END
  END W6END[3]
  PIN W6END[4]
    DIRECTION INPUT ;
    USE SIGNAL ;
    ANTENNAGATEAREA 0.196500 ;
    PORT
      LAYER met2 ;
        RECT 438.010 -1.500 438.290 0.800 ;
    END
  END W6END[4]
  PIN W6END[5]
    DIRECTION INPUT ;
    USE SIGNAL ;
    ANTENNAGATEAREA 0.196500 ;
    PORT
      LAYER met3 ;
        RECT 499.200 91.840 501.500 92.440 ;
    END
  END W6END[5]
  PIN W6END[6]
    DIRECTION INPUT ;
    USE SIGNAL ;
    ANTENNAGATEAREA 0.196500 ;
    PORT
      LAYER met3 ;
        RECT 499.200 370.640 501.500 371.240 ;
    END
  END W6END[6]
  PIN W6END[7]
    DIRECTION INPUT ;
    USE SIGNAL ;
    ANTENNAGATEAREA 0.196500 ;
    PORT
      LAYER met3 ;
        RECT 499.200 387.640 501.500 388.240 ;
    END
  END W6END[7]
  PIN W6END[8]
    DIRECTION INPUT ;
    USE SIGNAL ;
    ANTENNAGATEAREA 0.196500 ;
    PORT
      LAYER met2 ;
        RECT 431.570 -1.500 431.850 0.800 ;
    END
  END W6END[8]
  PIN W6END[9]
    DIRECTION INPUT ;
    USE SIGNAL ;
    ANTENNAGATEAREA 0.196500 ;
    PORT
      LAYER met3 ;
        RECT 499.200 153.040 501.500 153.640 ;
    END
  END W6END[9]
  PIN WW4BEG[0]
    DIRECTION OUTPUT ;
    USE SIGNAL ;
    ANTENNADIFFAREA 0.445500 ;
    PORT
      LAYER met3 ;
        RECT -1.500 489.640 0.800 490.240 ;
    END
  END WW4BEG[0]
  PIN WW4BEG[10]
    DIRECTION OUTPUT ;
    USE SIGNAL ;
    ANTENNADIFFAREA 0.445500 ;
    PORT
      LAYER met3 ;
        RECT 499.200 401.240 501.500 401.840 ;
    END
  END WW4BEG[10]
  PIN WW4BEG[11]
    DIRECTION OUTPUT ;
    USE SIGNAL ;
    ANTENNADIFFAREA 0.445500 ;
    PORT
      LAYER met2 ;
        RECT 444.450 -1.500 444.730 0.800 ;
    END
  END WW4BEG[11]
  PIN WW4BEG[12]
    DIRECTION OUTPUT ;
    USE SIGNAL ;
    ANTENNADIFFAREA 1.336500 ;
    PORT
      LAYER met2 ;
        RECT 241.590 -1.500 241.870 0.800 ;
    END
  END WW4BEG[12]
  PIN WW4BEG[13]
    DIRECTION OUTPUT ;
    USE SIGNAL ;
    ANTENNADIFFAREA 1.782000 ;
    PORT
      LAYER met3 ;
        RECT 499.200 166.640 501.500 167.240 ;
    END
  END WW4BEG[13]
  PIN WW4BEG[14]
    DIRECTION OUTPUT ;
    USE SIGNAL ;
    ANTENNADIFFAREA 1.782000 ;
    PORT
      LAYER met2 ;
        RECT 157.870 -1.500 158.150 0.800 ;
    END
  END WW4BEG[14]
  PIN WW4BEG[15]
    DIRECTION OUTPUT ;
    USE SIGNAL ;
    ANTENNADIFFAREA 1.782000 ;
    PORT
      LAYER met3 ;
        RECT 499.200 176.840 501.500 177.440 ;
    END
  END WW4BEG[15]
  PIN WW4BEG[1]
    DIRECTION OUTPUT ;
    USE SIGNAL ;
    ANTENNADIFFAREA 0.445500 ;
    PORT
      LAYER met3 ;
        RECT 499.200 319.640 501.500 320.240 ;
    END
  END WW4BEG[1]
  PIN WW4BEG[2]
    DIRECTION OUTPUT ;
    USE SIGNAL ;
    ANTENNADIFFAREA 0.445500 ;
    PORT
      LAYER met2 ;
        RECT 331.750 499.200 332.030 501.500 ;
    END
  END WW4BEG[2]
  PIN WW4BEG[3]
    DIRECTION OUTPUT ;
    USE SIGNAL ;
    ANTENNADIFFAREA 0.445500 ;
    PORT
      LAYER met3 ;
        RECT 499.200 139.440 501.500 140.040 ;
    END
  END WW4BEG[3]
  PIN WW4BEG[4]
    DIRECTION OUTPUT ;
    USE SIGNAL ;
    ANTENNADIFFAREA 0.445500 ;
    PORT
      LAYER met2 ;
        RECT 167.530 499.200 167.810 501.500 ;
    END
  END WW4BEG[4]
  PIN WW4BEG[5]
    DIRECTION OUTPUT ;
    USE SIGNAL ;
    ANTENNADIFFAREA 0.445500 ;
    PORT
      LAYER met3 ;
        RECT 499.200 418.240 501.500 418.840 ;
    END
  END WW4BEG[5]
  PIN WW4BEG[6]
    DIRECTION OUTPUT ;
    USE SIGNAL ;
    ANTENNADIFFAREA 0.445500 ;
    PORT
      LAYER met2 ;
        RECT 29.070 -1.500 29.350 0.800 ;
    END
  END WW4BEG[6]
  PIN WW4BEG[7]
    DIRECTION OUTPUT ;
    USE SIGNAL ;
    ANTENNADIFFAREA 0.445500 ;
    PORT
      LAYER met2 ;
        RECT 135.330 -1.500 135.610 0.800 ;
    END
  END WW4BEG[7]
  PIN WW4BEG[8]
    DIRECTION OUTPUT ;
    USE SIGNAL ;
    ANTENNADIFFAREA 0.445500 ;
    PORT
      LAYER met3 ;
        RECT -1.500 435.240 0.800 435.840 ;
    END
  END WW4BEG[8]
  PIN WW4BEG[9]
    DIRECTION OUTPUT ;
    USE SIGNAL ;
    ANTENNADIFFAREA 0.445500 ;
    PORT
      LAYER met3 ;
        RECT 499.200 316.240 501.500 316.840 ;
    END
  END WW4BEG[9]
  PIN WW4END[0]
    DIRECTION INPUT ;
    USE SIGNAL ;
    ANTENNAGATEAREA 0.213000 ;
    PORT
      LAYER met3 ;
        RECT -1.500 319.640 0.800 320.240 ;
    END
  END WW4END[0]
  PIN WW4END[10]
    DIRECTION INPUT ;
    USE SIGNAL ;
    ANTENNAGATEAREA 0.196500 ;
    PORT
      LAYER met2 ;
        RECT 12.970 -1.500 13.250 0.800 ;
    END
  END WW4END[10]
  PIN WW4END[11]
    DIRECTION INPUT ;
    USE SIGNAL ;
    ANTENNAGATEAREA 0.196500 ;
    PORT
      LAYER met2 ;
        RECT 132.110 -1.500 132.390 0.800 ;
    END
  END WW4END[11]
  PIN WW4END[12]
    DIRECTION INPUT ;
    USE SIGNAL ;
    ANTENNAGATEAREA 0.196500 ;
    PORT
      LAYER met3 ;
        RECT -1.500 302.640 0.800 303.240 ;
    END
  END WW4END[12]
  PIN WW4END[13]
    DIRECTION INPUT ;
    USE SIGNAL ;
    ANTENNAGATEAREA 0.196500 ;
    PORT
      LAYER met3 ;
        RECT 499.200 384.240 501.500 384.840 ;
    END
  END WW4END[13]
  PIN WW4END[14]
    DIRECTION INPUT ;
    USE SIGNAL ;
    ANTENNAGATEAREA 0.196500 ;
    PORT
      LAYER met3 ;
        RECT 499.200 425.040 501.500 425.640 ;
    END
  END WW4END[14]
  PIN WW4END[15]
    DIRECTION INPUT ;
    USE SIGNAL ;
    ANTENNAGATEAREA 0.196500 ;
    PORT
      LAYER met2 ;
        RECT 441.230 -1.500 441.510 0.800 ;
    END
  END WW4END[15]
  PIN WW4END[1]
    DIRECTION INPUT ;
    USE SIGNAL ;
    ANTENNAGATEAREA 0.213000 ;
    PORT
      LAYER met3 ;
        RECT -1.500 282.240 0.800 282.840 ;
    END
  END WW4END[1]
  PIN WW4END[2]
    DIRECTION INPUT ;
    USE SIGNAL ;
    ANTENNAGATEAREA 0.213000 ;
    PORT
      LAYER met3 ;
        RECT -1.500 306.040 0.800 306.640 ;
    END
  END WW4END[2]
  PIN WW4END[3]
    DIRECTION INPUT ;
    USE SIGNAL ;
    ANTENNAGATEAREA 0.159000 ;
    PORT
      LAYER met3 ;
        RECT -1.500 176.840 0.800 177.440 ;
    END
  END WW4END[3]
  PIN WW4END[4]
    DIRECTION INPUT ;
    USE SIGNAL ;
    ANTENNAGATEAREA 0.196500 ;
    PORT
      LAYER met3 ;
        RECT -1.500 469.240 0.800 469.840 ;
    END
  END WW4END[4]
  PIN WW4END[5]
    DIRECTION INPUT ;
    USE SIGNAL ;
    ANTENNAGATEAREA 0.196500 ;
    PORT
      LAYER met3 ;
        RECT 499.200 377.440 501.500 378.040 ;
    END
  END WW4END[5]
  PIN WW4END[6]
    DIRECTION INPUT ;
    USE SIGNAL ;
    ANTENNAGATEAREA 0.196500 ;
    PORT
      LAYER met2 ;
        RECT 315.650 499.200 315.930 501.500 ;
    END
  END WW4END[6]
  PIN WW4END[7]
    DIRECTION INPUT ;
    USE SIGNAL ;
    ANTENNAGATEAREA 0.196500 ;
    PORT
      LAYER met3 ;
        RECT 499.200 170.040 501.500 170.640 ;
    END
  END WW4END[7]
  PIN WW4END[8]
    DIRECTION INPUT ;
    USE SIGNAL ;
    ANTENNAGATEAREA 0.196500 ;
    PORT
      LAYER met2 ;
        RECT 164.310 499.200 164.590 501.500 ;
    END
  END WW4END[8]
  PIN WW4END[9]
    DIRECTION INPUT ;
    USE SIGNAL ;
    ANTENNAGATEAREA 0.196500 ;
    PORT
      LAYER met3 ;
        RECT 499.200 421.640 501.500 422.240 ;
    END
  END WW4END[9]
  OBS
      LAYER nwell ;
        RECT 4.870 5.355 495.150 492.510 ;
      LAYER li1 ;
        RECT 5.060 5.355 494.960 492.405 ;
      LAYER met1 ;
        RECT 1.450 4.460 497.650 492.960 ;
      LAYER met2 ;
        RECT 1.470 498.920 54.550 499.530 ;
        RECT 55.390 498.920 57.770 499.530 ;
        RECT 58.610 498.920 60.990 499.530 ;
        RECT 61.830 498.920 64.210 499.530 ;
        RECT 65.050 498.920 67.430 499.530 ;
        RECT 68.270 498.920 70.650 499.530 ;
        RECT 71.490 498.920 73.870 499.530 ;
        RECT 74.710 498.920 77.090 499.530 ;
        RECT 77.930 498.920 80.310 499.530 ;
        RECT 81.150 498.920 83.530 499.530 ;
        RECT 84.370 498.920 86.750 499.530 ;
        RECT 87.590 498.920 89.970 499.530 ;
        RECT 90.810 498.920 93.190 499.530 ;
        RECT 94.030 498.920 96.410 499.530 ;
        RECT 97.250 498.920 99.630 499.530 ;
        RECT 100.470 498.920 102.850 499.530 ;
        RECT 103.690 498.920 106.070 499.530 ;
        RECT 106.910 498.920 109.290 499.530 ;
        RECT 110.130 498.920 112.510 499.530 ;
        RECT 113.350 498.920 115.730 499.530 ;
        RECT 116.570 498.920 118.950 499.530 ;
        RECT 119.790 498.920 122.170 499.530 ;
        RECT 123.010 498.920 125.390 499.530 ;
        RECT 126.230 498.920 128.610 499.530 ;
        RECT 129.450 498.920 131.830 499.530 ;
        RECT 132.670 498.920 135.050 499.530 ;
        RECT 135.890 498.920 138.270 499.530 ;
        RECT 139.110 498.920 141.490 499.530 ;
        RECT 142.330 498.920 144.710 499.530 ;
        RECT 145.550 498.920 147.930 499.530 ;
        RECT 148.770 498.920 151.150 499.530 ;
        RECT 151.990 498.920 154.370 499.530 ;
        RECT 155.210 498.920 157.590 499.530 ;
        RECT 158.430 498.920 160.810 499.530 ;
        RECT 161.650 498.920 164.030 499.530 ;
        RECT 164.870 498.920 167.250 499.530 ;
        RECT 168.090 498.920 170.470 499.530 ;
        RECT 171.310 498.920 173.690 499.530 ;
        RECT 174.530 498.920 176.910 499.530 ;
        RECT 177.750 498.920 180.130 499.530 ;
        RECT 180.970 498.920 183.350 499.530 ;
        RECT 184.190 498.920 186.570 499.530 ;
        RECT 187.410 498.920 189.790 499.530 ;
        RECT 190.630 498.920 193.010 499.530 ;
        RECT 193.850 498.920 196.230 499.530 ;
        RECT 197.070 498.920 199.450 499.530 ;
        RECT 200.290 498.920 202.670 499.530 ;
        RECT 203.510 498.920 205.890 499.530 ;
        RECT 206.730 498.920 209.110 499.530 ;
        RECT 209.950 498.920 212.330 499.530 ;
        RECT 213.170 498.920 215.550 499.530 ;
        RECT 216.390 498.920 218.770 499.530 ;
        RECT 219.610 498.920 221.990 499.530 ;
        RECT 222.830 498.920 225.210 499.530 ;
        RECT 226.050 498.920 228.430 499.530 ;
        RECT 229.270 498.920 231.650 499.530 ;
        RECT 232.490 498.920 234.870 499.530 ;
        RECT 235.710 498.920 238.090 499.530 ;
        RECT 238.930 498.920 241.310 499.530 ;
        RECT 242.150 498.920 244.530 499.530 ;
        RECT 245.370 498.920 247.750 499.530 ;
        RECT 248.590 498.920 250.970 499.530 ;
        RECT 251.810 498.920 254.190 499.530 ;
        RECT 255.030 498.920 257.410 499.530 ;
        RECT 258.250 498.920 260.630 499.530 ;
        RECT 261.470 498.920 263.850 499.530 ;
        RECT 264.690 498.920 267.070 499.530 ;
        RECT 267.910 498.920 270.290 499.530 ;
        RECT 271.130 498.920 273.510 499.530 ;
        RECT 274.350 498.920 276.730 499.530 ;
        RECT 277.570 498.920 279.950 499.530 ;
        RECT 280.790 498.920 283.170 499.530 ;
        RECT 284.010 498.920 286.390 499.530 ;
        RECT 287.230 498.920 289.610 499.530 ;
        RECT 290.450 498.920 292.830 499.530 ;
        RECT 293.670 498.920 296.050 499.530 ;
        RECT 296.890 498.920 299.270 499.530 ;
        RECT 300.110 498.920 302.490 499.530 ;
        RECT 303.330 498.920 305.710 499.530 ;
        RECT 306.550 498.920 308.930 499.530 ;
        RECT 309.770 498.920 312.150 499.530 ;
        RECT 312.990 498.920 315.370 499.530 ;
        RECT 316.210 498.920 318.590 499.530 ;
        RECT 319.430 498.920 321.810 499.530 ;
        RECT 322.650 498.920 325.030 499.530 ;
        RECT 325.870 498.920 328.250 499.530 ;
        RECT 329.090 498.920 331.470 499.530 ;
        RECT 332.310 498.920 334.690 499.530 ;
        RECT 335.530 498.920 337.910 499.530 ;
        RECT 338.750 498.920 341.130 499.530 ;
        RECT 341.970 498.920 344.350 499.530 ;
        RECT 345.190 498.920 347.570 499.530 ;
        RECT 348.410 498.920 350.790 499.530 ;
        RECT 351.630 498.920 354.010 499.530 ;
        RECT 354.850 498.920 357.230 499.530 ;
        RECT 358.070 498.920 360.450 499.530 ;
        RECT 361.290 498.920 363.670 499.530 ;
        RECT 364.510 498.920 366.890 499.530 ;
        RECT 367.730 498.920 370.110 499.530 ;
        RECT 370.950 498.920 373.330 499.530 ;
        RECT 374.170 498.920 376.550 499.530 ;
        RECT 377.390 498.920 379.770 499.530 ;
        RECT 380.610 498.920 382.990 499.530 ;
        RECT 383.830 498.920 386.210 499.530 ;
        RECT 387.050 498.920 389.430 499.530 ;
        RECT 390.270 498.920 392.650 499.530 ;
        RECT 393.490 498.920 395.870 499.530 ;
        RECT 396.710 498.920 399.090 499.530 ;
        RECT 399.930 498.920 402.310 499.530 ;
        RECT 403.150 498.920 405.530 499.530 ;
        RECT 406.370 498.920 408.750 499.530 ;
        RECT 409.590 498.920 411.970 499.530 ;
        RECT 412.810 498.920 415.190 499.530 ;
        RECT 416.030 498.920 418.410 499.530 ;
        RECT 419.250 498.920 421.630 499.530 ;
        RECT 422.470 498.920 497.630 499.530 ;
        RECT 1.470 1.080 497.630 498.920 ;
        RECT 1.470 0.270 12.690 1.080 ;
        RECT 13.530 0.270 15.910 1.080 ;
        RECT 16.750 0.270 19.130 1.080 ;
        RECT 19.970 0.270 22.350 1.080 ;
        RECT 23.190 0.270 25.570 1.080 ;
        RECT 26.410 0.270 28.790 1.080 ;
        RECT 29.630 0.270 99.630 1.080 ;
        RECT 100.470 0.270 102.850 1.080 ;
        RECT 103.690 0.270 106.070 1.080 ;
        RECT 106.910 0.270 112.510 1.080 ;
        RECT 113.350 0.270 118.950 1.080 ;
        RECT 119.790 0.270 122.170 1.080 ;
        RECT 123.010 0.270 128.610 1.080 ;
        RECT 129.450 0.270 131.830 1.080 ;
        RECT 132.670 0.270 135.050 1.080 ;
        RECT 135.890 0.270 138.270 1.080 ;
        RECT 139.110 0.270 141.490 1.080 ;
        RECT 142.330 0.270 144.710 1.080 ;
        RECT 145.550 0.270 151.150 1.080 ;
        RECT 151.990 0.270 154.370 1.080 ;
        RECT 155.210 0.270 157.590 1.080 ;
        RECT 158.430 0.270 160.810 1.080 ;
        RECT 161.650 0.270 164.030 1.080 ;
        RECT 164.870 0.270 167.250 1.080 ;
        RECT 168.090 0.270 170.470 1.080 ;
        RECT 171.310 0.270 173.690 1.080 ;
        RECT 174.530 0.270 176.910 1.080 ;
        RECT 177.750 0.270 180.130 1.080 ;
        RECT 180.970 0.270 183.350 1.080 ;
        RECT 184.190 0.270 186.570 1.080 ;
        RECT 187.410 0.270 189.790 1.080 ;
        RECT 190.630 0.270 193.010 1.080 ;
        RECT 193.850 0.270 196.230 1.080 ;
        RECT 197.070 0.270 199.450 1.080 ;
        RECT 200.290 0.270 202.670 1.080 ;
        RECT 203.510 0.270 205.890 1.080 ;
        RECT 206.730 0.270 209.110 1.080 ;
        RECT 209.950 0.270 212.330 1.080 ;
        RECT 213.170 0.270 215.550 1.080 ;
        RECT 216.390 0.270 218.770 1.080 ;
        RECT 219.610 0.270 221.990 1.080 ;
        RECT 222.830 0.270 225.210 1.080 ;
        RECT 226.050 0.270 228.430 1.080 ;
        RECT 229.270 0.270 231.650 1.080 ;
        RECT 232.490 0.270 234.870 1.080 ;
        RECT 235.710 0.270 238.090 1.080 ;
        RECT 238.930 0.270 241.310 1.080 ;
        RECT 242.150 0.270 244.530 1.080 ;
        RECT 245.370 0.270 247.750 1.080 ;
        RECT 248.590 0.270 250.970 1.080 ;
        RECT 251.810 0.270 254.190 1.080 ;
        RECT 255.030 0.270 257.410 1.080 ;
        RECT 258.250 0.270 260.630 1.080 ;
        RECT 261.470 0.270 263.850 1.080 ;
        RECT 264.690 0.270 267.070 1.080 ;
        RECT 267.910 0.270 270.290 1.080 ;
        RECT 271.130 0.270 273.510 1.080 ;
        RECT 274.350 0.270 276.730 1.080 ;
        RECT 277.570 0.270 279.950 1.080 ;
        RECT 280.790 0.270 283.170 1.080 ;
        RECT 284.010 0.270 286.390 1.080 ;
        RECT 287.230 0.270 289.610 1.080 ;
        RECT 290.450 0.270 292.830 1.080 ;
        RECT 293.670 0.270 296.050 1.080 ;
        RECT 296.890 0.270 299.270 1.080 ;
        RECT 300.110 0.270 302.490 1.080 ;
        RECT 303.330 0.270 305.710 1.080 ;
        RECT 306.550 0.270 308.930 1.080 ;
        RECT 309.770 0.270 312.150 1.080 ;
        RECT 312.990 0.270 315.370 1.080 ;
        RECT 316.210 0.270 318.590 1.080 ;
        RECT 319.430 0.270 321.810 1.080 ;
        RECT 322.650 0.270 325.030 1.080 ;
        RECT 325.870 0.270 328.250 1.080 ;
        RECT 329.090 0.270 331.470 1.080 ;
        RECT 332.310 0.270 334.690 1.080 ;
        RECT 335.530 0.270 337.910 1.080 ;
        RECT 338.750 0.270 341.130 1.080 ;
        RECT 341.970 0.270 344.350 1.080 ;
        RECT 345.190 0.270 347.570 1.080 ;
        RECT 348.410 0.270 350.790 1.080 ;
        RECT 351.630 0.270 354.010 1.080 ;
        RECT 354.850 0.270 357.230 1.080 ;
        RECT 358.070 0.270 360.450 1.080 ;
        RECT 361.290 0.270 363.670 1.080 ;
        RECT 364.510 0.270 366.890 1.080 ;
        RECT 367.730 0.270 370.110 1.080 ;
        RECT 370.950 0.270 373.330 1.080 ;
        RECT 374.170 0.270 376.550 1.080 ;
        RECT 377.390 0.270 379.770 1.080 ;
        RECT 380.610 0.270 382.990 1.080 ;
        RECT 383.830 0.270 386.210 1.080 ;
        RECT 387.050 0.270 389.430 1.080 ;
        RECT 390.270 0.270 392.650 1.080 ;
        RECT 393.490 0.270 405.530 1.080 ;
        RECT 406.370 0.270 408.750 1.080 ;
        RECT 409.590 0.270 411.970 1.080 ;
        RECT 412.810 0.270 415.190 1.080 ;
        RECT 416.030 0.270 418.410 1.080 ;
        RECT 419.250 0.270 421.630 1.080 ;
        RECT 422.470 0.270 424.850 1.080 ;
        RECT 425.690 0.270 428.070 1.080 ;
        RECT 428.910 0.270 431.290 1.080 ;
        RECT 432.130 0.270 434.510 1.080 ;
        RECT 435.350 0.270 437.730 1.080 ;
        RECT 438.570 0.270 440.950 1.080 ;
        RECT 441.790 0.270 444.170 1.080 ;
        RECT 445.010 0.270 447.390 1.080 ;
        RECT 448.230 0.270 450.610 1.080 ;
        RECT 451.450 0.270 453.830 1.080 ;
        RECT 454.670 0.270 457.050 1.080 ;
        RECT 457.890 0.270 460.270 1.080 ;
        RECT 461.110 0.270 463.490 1.080 ;
        RECT 464.330 0.270 466.710 1.080 ;
        RECT 467.550 0.270 469.930 1.080 ;
        RECT 470.770 0.270 473.150 1.080 ;
        RECT 473.990 0.270 476.370 1.080 ;
        RECT 477.210 0.270 479.590 1.080 ;
        RECT 480.430 0.270 482.810 1.080 ;
        RECT 483.650 0.270 486.030 1.080 ;
        RECT 486.870 0.270 489.250 1.080 ;
        RECT 490.090 0.270 492.470 1.080 ;
        RECT 493.310 0.270 495.690 1.080 ;
        RECT 496.530 0.270 497.630 1.080 ;
      LAYER met3 ;
        RECT 0.800 496.040 498.800 496.905 ;
        RECT 0.800 494.040 499.750 496.040 ;
        RECT 1.200 492.640 498.800 494.040 ;
        RECT 0.800 490.640 499.750 492.640 ;
        RECT 1.200 489.240 498.800 490.640 ;
        RECT 0.800 487.240 499.750 489.240 ;
        RECT 1.200 485.840 498.800 487.240 ;
        RECT 0.800 483.840 499.750 485.840 ;
        RECT 1.200 482.440 498.800 483.840 ;
        RECT 0.800 480.440 499.750 482.440 ;
        RECT 1.200 479.040 498.800 480.440 ;
        RECT 0.800 477.040 499.750 479.040 ;
        RECT 1.200 475.640 498.800 477.040 ;
        RECT 0.800 473.640 499.750 475.640 ;
        RECT 1.200 472.240 498.800 473.640 ;
        RECT 0.800 470.240 499.750 472.240 ;
        RECT 1.200 468.840 498.800 470.240 ;
        RECT 0.800 466.840 499.750 468.840 ;
        RECT 0.800 465.440 498.800 466.840 ;
        RECT 0.800 463.440 499.750 465.440 ;
        RECT 0.800 462.040 498.800 463.440 ;
        RECT 0.800 460.040 499.750 462.040 ;
        RECT 0.800 458.640 498.800 460.040 ;
        RECT 0.800 456.640 499.750 458.640 ;
        RECT 0.800 455.240 498.800 456.640 ;
        RECT 0.800 453.240 499.750 455.240 ;
        RECT 0.800 451.840 498.800 453.240 ;
        RECT 0.800 449.840 499.750 451.840 ;
        RECT 0.800 448.440 498.800 449.840 ;
        RECT 0.800 446.440 499.750 448.440 ;
        RECT 0.800 445.040 498.800 446.440 ;
        RECT 0.800 443.040 499.750 445.040 ;
        RECT 0.800 441.640 498.800 443.040 ;
        RECT 0.800 439.640 499.750 441.640 ;
        RECT 1.200 438.240 498.800 439.640 ;
        RECT 0.800 436.240 499.750 438.240 ;
        RECT 1.200 434.840 498.800 436.240 ;
        RECT 0.800 432.840 499.750 434.840 ;
        RECT 1.200 431.440 498.800 432.840 ;
        RECT 0.800 429.440 499.750 431.440 ;
        RECT 1.200 428.040 498.800 429.440 ;
        RECT 0.800 426.040 499.750 428.040 ;
        RECT 1.200 424.640 498.800 426.040 ;
        RECT 0.800 422.640 499.750 424.640 ;
        RECT 1.200 421.240 498.800 422.640 ;
        RECT 0.800 419.240 499.750 421.240 ;
        RECT 1.200 417.840 498.800 419.240 ;
        RECT 0.800 415.840 499.750 417.840 ;
        RECT 1.200 414.440 498.800 415.840 ;
        RECT 0.800 412.440 499.750 414.440 ;
        RECT 1.200 411.040 498.800 412.440 ;
        RECT 0.800 409.040 499.750 411.040 ;
        RECT 1.200 407.640 498.800 409.040 ;
        RECT 0.800 405.640 499.750 407.640 ;
        RECT 1.200 404.240 498.800 405.640 ;
        RECT 0.800 402.240 499.750 404.240 ;
        RECT 1.200 400.840 498.800 402.240 ;
        RECT 0.800 398.840 499.750 400.840 ;
        RECT 1.200 397.440 498.800 398.840 ;
        RECT 0.800 395.440 499.750 397.440 ;
        RECT 1.200 394.040 498.800 395.440 ;
        RECT 0.800 392.040 499.750 394.040 ;
        RECT 1.200 390.640 498.800 392.040 ;
        RECT 0.800 388.640 499.750 390.640 ;
        RECT 1.200 387.240 498.800 388.640 ;
        RECT 0.800 385.240 499.750 387.240 ;
        RECT 1.200 383.840 498.800 385.240 ;
        RECT 0.800 381.840 499.750 383.840 ;
        RECT 1.200 380.440 498.800 381.840 ;
        RECT 0.800 378.440 499.750 380.440 ;
        RECT 1.200 377.040 498.800 378.440 ;
        RECT 0.800 375.040 499.750 377.040 ;
        RECT 1.200 373.640 498.800 375.040 ;
        RECT 0.800 371.640 499.750 373.640 ;
        RECT 1.200 370.240 498.800 371.640 ;
        RECT 0.800 368.240 499.750 370.240 ;
        RECT 1.200 366.840 498.800 368.240 ;
        RECT 0.800 364.840 499.750 366.840 ;
        RECT 1.200 363.440 498.800 364.840 ;
        RECT 0.800 361.440 499.750 363.440 ;
        RECT 1.200 360.040 498.800 361.440 ;
        RECT 0.800 358.040 499.750 360.040 ;
        RECT 1.200 356.640 498.800 358.040 ;
        RECT 0.800 354.640 499.750 356.640 ;
        RECT 1.200 353.240 498.800 354.640 ;
        RECT 0.800 351.240 499.750 353.240 ;
        RECT 1.200 349.840 498.800 351.240 ;
        RECT 0.800 347.840 499.750 349.840 ;
        RECT 1.200 346.440 498.800 347.840 ;
        RECT 0.800 344.440 499.750 346.440 ;
        RECT 1.200 343.040 498.800 344.440 ;
        RECT 0.800 341.040 499.750 343.040 ;
        RECT 1.200 339.640 498.800 341.040 ;
        RECT 0.800 337.640 499.750 339.640 ;
        RECT 1.200 336.240 498.800 337.640 ;
        RECT 0.800 334.240 499.750 336.240 ;
        RECT 1.200 332.840 498.800 334.240 ;
        RECT 0.800 330.840 499.750 332.840 ;
        RECT 1.200 329.440 498.800 330.840 ;
        RECT 0.800 327.440 499.750 329.440 ;
        RECT 1.200 326.040 498.800 327.440 ;
        RECT 0.800 324.040 499.750 326.040 ;
        RECT 1.200 322.640 498.800 324.040 ;
        RECT 0.800 320.640 499.750 322.640 ;
        RECT 1.200 319.240 498.800 320.640 ;
        RECT 0.800 317.240 499.750 319.240 ;
        RECT 1.200 315.840 498.800 317.240 ;
        RECT 0.800 313.840 499.750 315.840 ;
        RECT 1.200 312.440 498.800 313.840 ;
        RECT 0.800 310.440 499.750 312.440 ;
        RECT 1.200 309.040 498.800 310.440 ;
        RECT 0.800 307.040 499.750 309.040 ;
        RECT 1.200 305.640 498.800 307.040 ;
        RECT 0.800 303.640 499.750 305.640 ;
        RECT 1.200 302.240 498.800 303.640 ;
        RECT 0.800 300.240 499.750 302.240 ;
        RECT 1.200 298.840 498.800 300.240 ;
        RECT 0.800 296.840 499.750 298.840 ;
        RECT 1.200 295.440 498.800 296.840 ;
        RECT 0.800 293.440 499.750 295.440 ;
        RECT 1.200 292.040 498.800 293.440 ;
        RECT 0.800 290.040 499.750 292.040 ;
        RECT 1.200 288.640 498.800 290.040 ;
        RECT 0.800 286.640 499.750 288.640 ;
        RECT 1.200 285.240 498.800 286.640 ;
        RECT 0.800 283.240 499.750 285.240 ;
        RECT 1.200 281.840 498.800 283.240 ;
        RECT 0.800 279.840 499.750 281.840 ;
        RECT 1.200 278.440 498.800 279.840 ;
        RECT 0.800 276.440 499.750 278.440 ;
        RECT 1.200 275.040 498.800 276.440 ;
        RECT 0.800 273.040 499.750 275.040 ;
        RECT 1.200 271.640 498.800 273.040 ;
        RECT 0.800 269.640 499.750 271.640 ;
        RECT 1.200 268.240 498.800 269.640 ;
        RECT 0.800 266.240 499.750 268.240 ;
        RECT 1.200 264.840 498.800 266.240 ;
        RECT 0.800 262.840 499.750 264.840 ;
        RECT 1.200 261.440 498.800 262.840 ;
        RECT 0.800 259.440 499.750 261.440 ;
        RECT 1.200 258.040 498.800 259.440 ;
        RECT 0.800 256.040 499.750 258.040 ;
        RECT 1.200 254.640 498.800 256.040 ;
        RECT 0.800 252.640 499.750 254.640 ;
        RECT 1.200 251.240 498.800 252.640 ;
        RECT 0.800 249.240 499.750 251.240 ;
        RECT 1.200 247.840 498.800 249.240 ;
        RECT 0.800 245.840 499.750 247.840 ;
        RECT 1.200 244.440 498.800 245.840 ;
        RECT 0.800 242.440 499.750 244.440 ;
        RECT 1.200 241.040 498.800 242.440 ;
        RECT 0.800 239.040 499.750 241.040 ;
        RECT 1.200 237.640 498.800 239.040 ;
        RECT 0.800 235.640 499.750 237.640 ;
        RECT 1.200 234.240 498.800 235.640 ;
        RECT 0.800 232.240 499.750 234.240 ;
        RECT 1.200 230.840 498.800 232.240 ;
        RECT 0.800 228.840 499.750 230.840 ;
        RECT 1.200 227.440 498.800 228.840 ;
        RECT 0.800 225.440 499.750 227.440 ;
        RECT 1.200 224.040 498.800 225.440 ;
        RECT 0.800 222.040 499.750 224.040 ;
        RECT 1.200 220.640 498.800 222.040 ;
        RECT 0.800 218.640 499.750 220.640 ;
        RECT 1.200 217.240 498.800 218.640 ;
        RECT 0.800 215.240 499.750 217.240 ;
        RECT 1.200 213.840 498.800 215.240 ;
        RECT 0.800 211.840 499.750 213.840 ;
        RECT 1.200 210.440 498.800 211.840 ;
        RECT 0.800 208.440 499.750 210.440 ;
        RECT 1.200 207.040 498.800 208.440 ;
        RECT 0.800 205.040 499.750 207.040 ;
        RECT 1.200 203.640 498.800 205.040 ;
        RECT 0.800 201.640 499.750 203.640 ;
        RECT 1.200 200.240 498.800 201.640 ;
        RECT 0.800 198.240 499.750 200.240 ;
        RECT 1.200 196.840 498.800 198.240 ;
        RECT 0.800 194.840 499.750 196.840 ;
        RECT 1.200 193.440 498.800 194.840 ;
        RECT 0.800 191.440 499.750 193.440 ;
        RECT 1.200 190.040 498.800 191.440 ;
        RECT 0.800 188.040 499.750 190.040 ;
        RECT 1.200 186.640 498.800 188.040 ;
        RECT 0.800 184.640 499.750 186.640 ;
        RECT 1.200 183.240 498.800 184.640 ;
        RECT 0.800 181.240 499.750 183.240 ;
        RECT 1.200 179.840 498.800 181.240 ;
        RECT 0.800 177.840 499.750 179.840 ;
        RECT 1.200 176.440 498.800 177.840 ;
        RECT 0.800 174.440 499.750 176.440 ;
        RECT 1.200 173.040 498.800 174.440 ;
        RECT 0.800 171.040 499.750 173.040 ;
        RECT 1.200 169.640 498.800 171.040 ;
        RECT 0.800 167.640 499.750 169.640 ;
        RECT 1.200 166.240 498.800 167.640 ;
        RECT 0.800 164.240 499.750 166.240 ;
        RECT 1.200 162.840 498.800 164.240 ;
        RECT 0.800 160.840 499.750 162.840 ;
        RECT 1.200 159.440 498.800 160.840 ;
        RECT 0.800 157.440 499.750 159.440 ;
        RECT 1.200 156.040 498.800 157.440 ;
        RECT 0.800 154.040 499.750 156.040 ;
        RECT 1.200 152.640 498.800 154.040 ;
        RECT 0.800 150.640 499.750 152.640 ;
        RECT 1.200 149.240 498.800 150.640 ;
        RECT 0.800 147.240 499.750 149.240 ;
        RECT 1.200 145.840 498.800 147.240 ;
        RECT 0.800 143.840 499.750 145.840 ;
        RECT 1.200 142.440 498.800 143.840 ;
        RECT 0.800 140.440 499.750 142.440 ;
        RECT 1.200 139.040 498.800 140.440 ;
        RECT 0.800 137.040 499.750 139.040 ;
        RECT 1.200 135.640 498.800 137.040 ;
        RECT 0.800 133.640 499.750 135.640 ;
        RECT 1.200 132.240 498.800 133.640 ;
        RECT 0.800 130.240 499.750 132.240 ;
        RECT 1.200 128.840 498.800 130.240 ;
        RECT 0.800 126.840 499.750 128.840 ;
        RECT 1.200 125.440 498.800 126.840 ;
        RECT 0.800 123.440 499.750 125.440 ;
        RECT 1.200 122.040 498.800 123.440 ;
        RECT 0.800 120.040 499.750 122.040 ;
        RECT 1.200 118.640 498.800 120.040 ;
        RECT 0.800 116.640 499.750 118.640 ;
        RECT 1.200 115.240 498.800 116.640 ;
        RECT 0.800 113.240 499.750 115.240 ;
        RECT 1.200 111.840 498.800 113.240 ;
        RECT 0.800 109.840 499.750 111.840 ;
        RECT 1.200 108.440 498.800 109.840 ;
        RECT 0.800 106.440 499.750 108.440 ;
        RECT 1.200 105.040 498.800 106.440 ;
        RECT 0.800 103.040 499.750 105.040 ;
        RECT 1.200 101.640 498.800 103.040 ;
        RECT 0.800 99.640 499.750 101.640 ;
        RECT 1.200 98.240 498.800 99.640 ;
        RECT 0.800 96.240 499.750 98.240 ;
        RECT 1.200 94.840 498.800 96.240 ;
        RECT 0.800 92.840 499.750 94.840 ;
        RECT 1.200 91.440 498.800 92.840 ;
        RECT 0.800 89.440 499.750 91.440 ;
        RECT 1.200 88.040 498.800 89.440 ;
        RECT 0.800 86.040 499.750 88.040 ;
        RECT 1.200 84.640 498.800 86.040 ;
        RECT 0.800 82.640 499.750 84.640 ;
        RECT 1.200 81.240 498.800 82.640 ;
        RECT 0.800 79.240 499.750 81.240 ;
        RECT 1.200 77.840 498.800 79.240 ;
        RECT 0.800 75.840 499.750 77.840 ;
        RECT 1.200 74.440 498.800 75.840 ;
        RECT 0.800 72.440 499.750 74.440 ;
        RECT 1.200 71.040 498.800 72.440 ;
        RECT 0.800 69.040 499.750 71.040 ;
        RECT 1.200 67.640 498.800 69.040 ;
        RECT 0.800 65.640 499.750 67.640 ;
        RECT 1.200 64.240 498.800 65.640 ;
        RECT 0.800 62.240 499.750 64.240 ;
        RECT 1.200 60.840 498.800 62.240 ;
        RECT 0.800 58.840 499.750 60.840 ;
        RECT 1.200 57.440 498.800 58.840 ;
        RECT 0.800 55.440 499.750 57.440 ;
        RECT 1.200 54.040 498.800 55.440 ;
        RECT 0.800 52.040 499.750 54.040 ;
        RECT 1.200 50.640 498.800 52.040 ;
        RECT 0.800 48.640 499.750 50.640 ;
        RECT 1.200 47.240 498.800 48.640 ;
        RECT 0.800 45.240 499.750 47.240 ;
        RECT 1.200 43.840 498.800 45.240 ;
        RECT 0.800 41.840 499.750 43.840 ;
        RECT 1.200 40.440 498.800 41.840 ;
        RECT 0.800 38.440 499.750 40.440 ;
        RECT 1.200 37.040 498.800 38.440 ;
        RECT 0.800 35.040 499.750 37.040 ;
        RECT 0.800 33.640 498.800 35.040 ;
        RECT 0.800 31.640 499.750 33.640 ;
        RECT 0.800 30.240 498.800 31.640 ;
        RECT 0.800 24.840 499.750 30.240 ;
        RECT 0.800 23.440 498.800 24.840 ;
        RECT 0.800 21.440 499.750 23.440 ;
        RECT 0.800 20.040 498.800 21.440 ;
        RECT 0.800 18.040 499.750 20.040 ;
        RECT 0.800 16.640 498.800 18.040 ;
        RECT 0.800 14.640 499.750 16.640 ;
        RECT 0.800 13.240 498.800 14.640 ;
        RECT 0.800 11.240 499.750 13.240 ;
        RECT 0.800 9.840 498.800 11.240 ;
        RECT 0.800 5.275 499.750 9.840 ;
      LAYER met4 ;
        RECT 59.175 6.295 173.780 365.665 ;
        RECT 176.180 6.295 177.080 365.665 ;
        RECT 179.480 6.295 327.380 365.665 ;
        RECT 329.780 6.295 330.680 365.665 ;
        RECT 333.080 6.295 364.025 365.665 ;
  END
END LUT4AB
END LIBRARY

